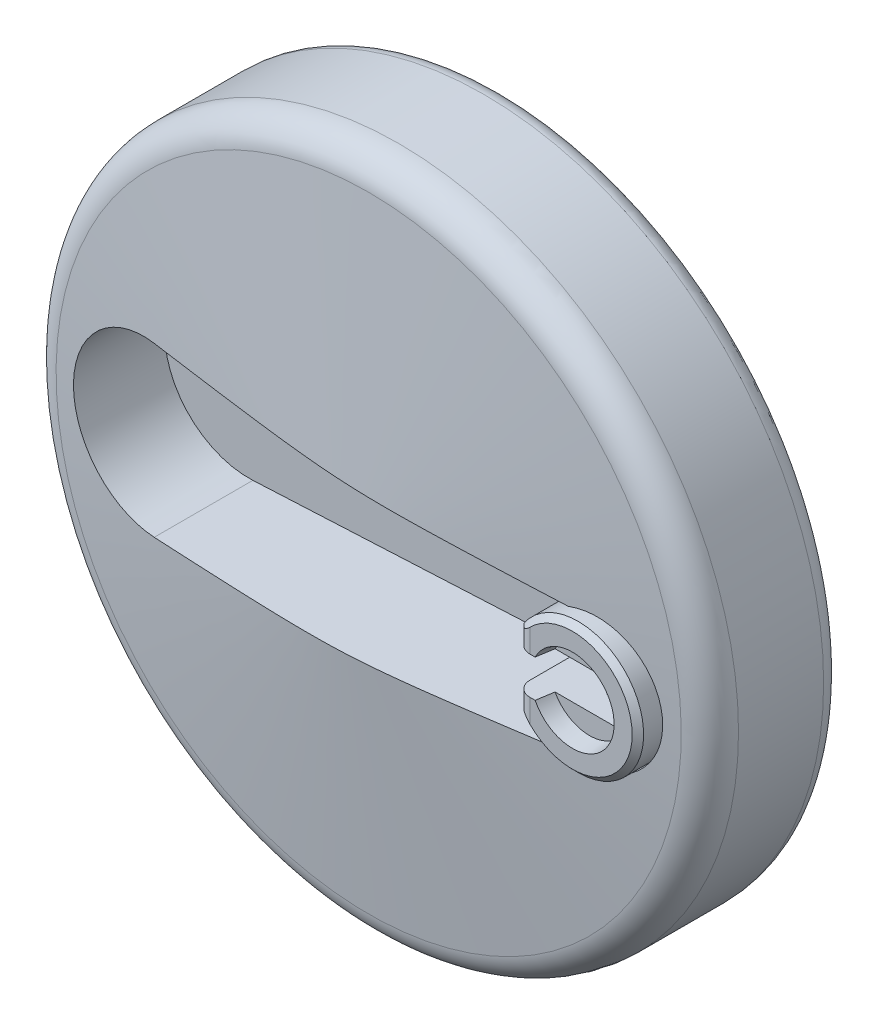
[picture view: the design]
ISO-10303-21;
HEADER;
FILE_DESCRIPTION(('STEP AP214'),'2;1');
FILE_NAME('part.step','',(''),(''),'','','');
FILE_SCHEMA(('AUTOMOTIVE_DESIGN { 1 0 10303 214 1 1 1 1 }'));
ENDSEC;
DATA;
#1=APPLICATION_CONTEXT('core data for automotive mechanical design processes');
#2=APPLICATION_PROTOCOL_DEFINITION('international standard','automotive_design',2000,#1);
#3=PRODUCT_CONTEXT('',#1,'mechanical');
#4=PRODUCT('Part','Part','',(#3));
#5=PRODUCT_RELATED_PRODUCT_CATEGORY('part','',(#4));
#6=PRODUCT_DEFINITION_FORMATION('','',#4);
#7=PRODUCT_DEFINITION_CONTEXT('part definition',#1,'design');
#8=PRODUCT_DEFINITION('design','',#6,#7);
#9=PRODUCT_DEFINITION_SHAPE('','',#8);
#10=(LENGTH_UNIT() NAMED_UNIT(*) SI_UNIT(.MILLI.,.METRE.));
#11=(NAMED_UNIT(*) PLANE_ANGLE_UNIT() SI_UNIT($,.RADIAN.));
#12=(NAMED_UNIT(*) SI_UNIT($,.STERADIAN.) SOLID_ANGLE_UNIT());
#13=UNCERTAINTY_MEASURE_WITH_UNIT(LENGTH_MEASURE(1.E-05),#10,'distance_accuracy_value','');
#14=(GEOMETRIC_REPRESENTATION_CONTEXT(3) GLOBAL_UNCERTAINTY_ASSIGNED_CONTEXT((#13)) GLOBAL_UNIT_ASSIGNED_CONTEXT((#10,
#11,#12)) REPRESENTATION_CONTEXT('',''));
#15=CARTESIAN_POINT('',(0.,0.,0.));
#16=DIRECTION('',(0.,0.,1.));
#17=DIRECTION('',(1.,0.,0.));
#18=AXIS2_PLACEMENT_3D('',#15,#16,#17);
#19=CARTESIAN_POINT('',(28.,0.,24.0000000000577));
#20=DIRECTION('',(0.,0.,-1.));
#21=DIRECTION('',(0.,-1.,0.));
#22=AXIS2_PLACEMENT_3D('',#19,#20,#21);
#23=CONICAL_SURFACE('',#22,1.99999999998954,0.785398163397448);
#24=CARTESIAN_POINT('',(28.,0.,24.));
#25=DIRECTION('',(0.,0.,1.));
#26=DIRECTION('',(0.,1.,0.));
#27=AXIS2_PLACEMENT_3D('',#24,#25,#26);
#28=CIRCLE('',#27,2.0000000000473);
#29=CARTESIAN_POINT('',(28.,2.0000000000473,24.));
#30=VERTEX_POINT('',#29);
#31=EDGE_CURVE('E27',#30,#30,#28,.T.);
#32=ORIENTED_EDGE('',*,*,#31,.F.);
#33=EDGE_LOOP('',(#32));
#34=FACE_BOUND('',#33,.T.);
#35=CARTESIAN_POINT('',(28.,0.,24.3790000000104));
#36=DIRECTION('',(0.,0.,-1.));
#37=DIRECTION('',(-1.,0.,0.));
#38=AXIS2_PLACEMENT_3D('',#35,#36,#37);
#39=CIRCLE('',#38,1.62100000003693);
#40=CARTESIAN_POINT('',(26.3789999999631,0.,24.3790000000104));
#41=VERTEX_POINT('',#40);
#42=EDGE_CURVE('E195',#41,#41,#39,.T.);
#43=ORIENTED_EDGE('',*,*,#42,.F.);
#44=EDGE_LOOP('',(#43));
#45=FACE_BOUND('',#44,.T.);
#46=ADVANCED_FACE('F16',(#34,#45),#23,.F.);
#47=CARTESIAN_POINT('',(28.,0.,26.));
#48=DIRECTION('',(0.,0.,-1.));
#49=DIRECTION('',(0.,-1.,0.));
#50=AXIS2_PLACEMENT_3D('',#47,#48,#49);
#51=CYLINDRICAL_SURFACE('',#50,1.621);
#52=ORIENTED_EDGE('',*,*,#42,.T.);
#53=EDGE_LOOP('',(#52));
#54=FACE_BOUND('',#53,.T.);
#55=CARTESIAN_POINT('',(28.,0.,27.6210000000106));
#56=DIRECTION('',(0.,0.,1.));
#57=DIRECTION('',(-1.,0.,0.));
#58=AXIS2_PLACEMENT_3D('',#55,#56,#57);
#59=CIRCLE('',#58,1.62100000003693);
#60=CARTESIAN_POINT('',(26.3789999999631,0.,27.6210000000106));
#61=VERTEX_POINT('',#60);
#62=EDGE_CURVE('E142',#61,#61,#59,.T.);
#63=ORIENTED_EDGE('',*,*,#62,.T.);
#64=EDGE_LOOP('',(#63));
#65=FACE_BOUND('',#64,.T.);
#66=ADVANCED_FACE('F249',(#54,#65),#51,.F.);
#67=CARTESIAN_POINT('',(28.,0.,30.65));
#68=DIRECTION('',(0.,0.,-1.));
#69=DIRECTION('',(0.,-1.,0.));
#70=AXIS2_PLACEMENT_3D('',#67,#68,#69);
#71=CYLINDRICAL_SURFACE('',#70,8.);
#72=CARTESIAN_POINT('',(29.6,7.83836717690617,31.5675675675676));
#73=CARTESIAN_POINT('',(29.5999957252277,7.83836939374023,31.6563778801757));
#74=CARTESIAN_POINT('',(29.5925737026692,7.83989440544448,31.7452985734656));
#75=CARTESIAN_POINT('',(29.5630860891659,7.84582557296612,31.9206956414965));
#76=CARTESIAN_POINT('',(29.540991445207,7.85023744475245,32.0071668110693));
#77=CARTESIAN_POINT('',(29.4828692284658,7.86142276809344,32.1749958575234));
#78=CARTESIAN_POINT('',(29.4468618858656,7.86819278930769,32.2563609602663));
#79=CARTESIAN_POINT('',(29.3619853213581,7.88332705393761,32.411868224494));
#80=CARTESIAN_POINT('',(29.3131203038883,7.89169077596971,32.4860127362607));
#81=CARTESIAN_POINT('',(29.2031679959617,7.90920456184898,32.6260630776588));
#82=CARTESIAN_POINT('',(29.1419323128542,7.91836331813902,32.6918513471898));
#83=CARTESIAN_POINT('',(29.0092946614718,7.93635908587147,32.8122967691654));
#84=CARTESIAN_POINT('',(28.937891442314,7.9451960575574,32.8669525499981));
#85=CARTESIAN_POINT('',(28.786177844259,7.96164477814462,32.9640285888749));
#86=CARTESIAN_POINT('',(28.7057954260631,7.96924520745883,33.0063383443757));
#87=CARTESIAN_POINT('',(28.538885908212,7.9822678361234,33.0768077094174));
#88=CARTESIAN_POINT('',(28.4523594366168,7.98769025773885,33.1049687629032));
#89=CARTESIAN_POINT('',(28.2768269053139,7.99568512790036,33.1459790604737));
#90=CARTESIAN_POINT('',(28.1878685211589,7.99829417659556,33.1590251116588));
#91=CARTESIAN_POINT('',(28.0089898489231,8.00049473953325,33.1700490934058));
#92=CARTESIAN_POINT('',(27.9190696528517,8.00008653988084,33.1680284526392));
#93=CARTESIAN_POINT('',(27.7421731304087,7.99632696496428,33.1491257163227));
#94=CARTESIAN_POINT('',(27.6551731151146,7.99301759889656,33.1324557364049));
#95=CARTESIAN_POINT('',(27.4852300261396,7.98387487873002,33.0850637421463));
#96=CARTESIAN_POINT('',(27.4022871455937,7.97804140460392,33.0543410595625));
#97=CARTESIAN_POINT('',(27.2422059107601,7.9644364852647,32.9795181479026));
#98=CARTESIAN_POINT('',(27.1651076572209,7.95665299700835,32.9353344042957));
#99=CARTESIAN_POINT('',(27.0193468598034,7.94000685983,32.8349088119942));
#100=CARTESIAN_POINT('',(26.9506846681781,7.93114416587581,32.7786664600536));
#101=CARTESIAN_POINT('',(26.8224914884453,7.91313735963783,32.6545674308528));
#102=CARTESIAN_POINT('',(26.7631384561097,7.90399103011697,32.5865271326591));
#103=CARTESIAN_POINT('',(26.6566304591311,7.88658867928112,32.4413329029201));
#104=CARTESIAN_POINT('',(26.6094809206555,7.87833305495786,32.3641749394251));
#105=CARTESIAN_POINT('',(26.5286594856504,7.86364139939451,32.202658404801));
#106=CARTESIAN_POINT('',(26.4950274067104,7.85721076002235,32.1182794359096));
#107=CARTESIAN_POINT('',(26.4425364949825,7.84697610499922,31.9450179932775));
#108=CARTESIAN_POINT('',(26.4236465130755,7.84316655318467,31.856145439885));
#109=CARTESIAN_POINT('',(26.4082711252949,7.84005162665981,31.7334243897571));
#110=CARTESIAN_POINT('',(26.4051721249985,7.83942144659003,31.7003365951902));
#111=CARTESIAN_POINT('',(26.4010357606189,7.83857880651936,31.6340268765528));
#112=CARTESIAN_POINT('',(26.3999984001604,7.8383663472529,31.6008049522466));
#113=CARTESIAN_POINT('',(26.4000042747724,7.83836939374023,31.4787572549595));
#114=CARTESIAN_POINT('',(26.4074262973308,7.83989440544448,31.3898365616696));
#115=CARTESIAN_POINT('',(26.4369139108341,7.84582557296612,31.2144394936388));
#116=CARTESIAN_POINT('',(26.459008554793,7.85023744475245,31.1279683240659));
#117=CARTESIAN_POINT('',(26.5171307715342,7.86142276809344,30.9601392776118));
#118=CARTESIAN_POINT('',(26.5531381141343,7.86819278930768,30.878774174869));
#119=CARTESIAN_POINT('',(26.6380146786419,7.88332705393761,30.7232669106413));
#120=CARTESIAN_POINT('',(26.6868796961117,7.89169077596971,30.6491223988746));
#121=CARTESIAN_POINT('',(26.7968320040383,7.90920456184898,30.5090720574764));
#122=CARTESIAN_POINT('',(26.8580676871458,7.91836331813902,30.4432837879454));
#123=CARTESIAN_POINT('',(26.9907053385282,7.93635908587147,30.3228383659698));
#124=CARTESIAN_POINT('',(27.062108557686,7.9451960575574,30.2681825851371));
#125=CARTESIAN_POINT('',(27.213822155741,7.96164477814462,30.1711065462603));
#126=CARTESIAN_POINT('',(27.2942045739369,7.96924520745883,30.1287967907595));
#127=CARTESIAN_POINT('',(27.461114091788,7.9822678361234,30.0583274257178));
#128=CARTESIAN_POINT('',(27.5476405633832,7.98769025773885,30.030166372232));
#129=CARTESIAN_POINT('',(27.7231730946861,7.99568512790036,29.9891560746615));
#130=CARTESIAN_POINT('',(27.8121314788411,7.99829417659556,29.9761100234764));
#131=CARTESIAN_POINT('',(27.9910101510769,8.00049473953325,29.9650860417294));
#132=CARTESIAN_POINT('',(28.0809303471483,8.00008653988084,29.967106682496));
#133=CARTESIAN_POINT('',(28.2578268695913,7.99632696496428,29.9860094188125));
#134=CARTESIAN_POINT('',(28.3448268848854,7.99301759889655,30.0026793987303));
#135=CARTESIAN_POINT('',(28.5147699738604,7.98387487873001,30.0500713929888));
#136=CARTESIAN_POINT('',(28.5977128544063,7.97804140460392,30.0807940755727));
#137=CARTESIAN_POINT('',(28.7577940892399,7.9644364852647,30.1556169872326));
#138=CARTESIAN_POINT('',(28.8348923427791,7.95665299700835,30.1998007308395));
#139=CARTESIAN_POINT('',(28.9806531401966,7.94000685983,30.300226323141));
#140=CARTESIAN_POINT('',(29.0493153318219,7.93114416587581,30.3564686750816));
#141=CARTESIAN_POINT('',(29.1775085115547,7.91313735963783,30.4805677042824));
#142=CARTESIAN_POINT('',(29.2368615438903,7.90399103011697,30.5486080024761));
#143=CARTESIAN_POINT('',(29.3433695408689,7.88658867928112,30.6938022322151));
#144=CARTESIAN_POINT('',(29.3905190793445,7.87833305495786,30.7709601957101));
#145=CARTESIAN_POINT('',(29.4713405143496,7.86364139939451,30.9324767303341));
#146=CARTESIAN_POINT('',(29.5049725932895,7.85721076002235,31.0168556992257));
#147=CARTESIAN_POINT('',(29.5574635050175,7.84697610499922,31.1901171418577));
#148=CARTESIAN_POINT('',(29.5763534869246,7.84316655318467,31.2789896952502));
#149=CARTESIAN_POINT('',(29.5917288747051,7.84005162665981,31.4017107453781));
#150=CARTESIAN_POINT('',(29.5948278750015,7.83942144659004,31.434798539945));
#151=CARTESIAN_POINT('',(29.5989642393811,7.83857880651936,31.5011082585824));
#152=CARTESIAN_POINT('',(29.6000015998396,7.8383663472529,31.5343301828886));
#153=CARTESIAN_POINT('',(29.6,7.83836717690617,31.5675675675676));
#154=B_SPLINE_CURVE_WITH_KNOTS('',3,(#72,#73,#74,#75,#76,#77,#78,#79,#80,#81,#82,#83,#84,#85,
#86,#87,#88,#89,#90,#91,#92,#93,#94,#95,#96,#97,#98,#99,#100,#101,#102,#103,#104,#105,#106,#107,
#108,#109,#110,#111,#112,#113,#114,#115,#116,#117,#118,#119,#120,#121,#122,#123,#124,#125,#126,
#127,#128,#129,#130,#131,#132,#133,#134,#135,#136,#137,#138,#139,#140,#141,#142,#143,#144,#145,
#146,#147,#148,#149,#150,#151,#152,#153),.UNSPECIFIED.,.T.,.F.,(4,2,2,2,2,2,2,2,2,2,2,2,2,2,2,2,
2,2,2,2,2,2,2,2,2,2,2,2,2,2,2,2,2,2,2,2,2,2,2,2,4),(0.,0.266303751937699,0.533136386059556,
0.799582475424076,1.06594154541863,1.33570888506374,1.60550944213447,1.87765555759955,
2.14977389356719,2.41830777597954,2.68681619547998,2.95149963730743,3.21619566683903,
3.48256856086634,3.74895257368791,4.01993197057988,4.29103164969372,4.56292413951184,
4.83424057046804,4.93390494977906,5.03356950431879,5.29987325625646,5.56670589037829,
5.83315197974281,6.09951104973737,6.3692783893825,6.63907894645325,6.91122506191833,
7.18334339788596,7.45187728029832,7.72038569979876,7.98506914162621,8.24976517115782,
8.51613806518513,8.7825220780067,9.05350147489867,9.32460115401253,9.59649364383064,
9.86781007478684,9.96747445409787,10.0671390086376),.UNSPECIFIED.);
#155=CARTESIAN_POINT('',(29.6,7.83836717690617,31.5675675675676));
#156=VERTEX_POINT('',#155);
#157=EDGE_CURVE('E230',#156,#156,#154,.T.);
#158=ORIENTED_EDGE('',*,*,#157,.T.);
#159=EDGE_LOOP('',(#158));
#160=FACE_BOUND('',#159,.T.);
#161=CARTESIAN_POINT('',(21.3854268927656,4.49971361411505,37.3));
#162=CARTESIAN_POINT('',(21.3611186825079,4.46398733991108,37.2688460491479));
#163=CARTESIAN_POINT('',(21.3375430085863,4.42870188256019,37.2365745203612));
#164=CARTESIAN_POINT('',(21.2919472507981,4.35932799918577,37.1695025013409));
#165=CARTESIAN_POINT('',(21.2699317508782,4.32524323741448,37.1346951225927));
#166=CARTESIAN_POINT('',(21.2271401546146,4.2579341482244,37.0614976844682));
#167=CARTESIAN_POINT('',(21.2064107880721,4.22475481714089,37.0230382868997));
#168=CARTESIAN_POINT('',(21.1671165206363,4.16090210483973,36.9431236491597));
#169=CARTESIAN_POINT('',(21.1485490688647,4.13022578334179,36.9016720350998));
#170=CARTESIAN_POINT('',(21.111194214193,4.0676625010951,36.8087047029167));
#171=CARTESIAN_POINT('',(21.092827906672,4.03633854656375,36.7566295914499));
#172=CARTESIAN_POINT('',(21.0604254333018,3.98036944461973,36.6484532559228));
#173=CARTESIAN_POINT('',(21.0463433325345,3.95565381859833,36.5924033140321));
#174=CARTESIAN_POINT('',(21.0237726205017,3.91570759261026,36.4786073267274));
#175=CARTESIAN_POINT('',(21.0150693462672,3.90011453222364,36.421038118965));
#176=CARTESIAN_POINT('',(21.0061393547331,3.88406371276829,36.3323796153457));
#177=CARTESIAN_POINT('',(21.0038487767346,3.87993353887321,36.3021352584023));
#178=CARTESIAN_POINT('',(21.0007746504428,3.87438362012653,36.2412691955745));
#179=CARTESIAN_POINT('',(20.9999938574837,3.87296883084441,36.2106469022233));
#180=CARTESIAN_POINT('',(21.,3.87298334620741,36.18));
#181=B_SPLINE_CURVE_WITH_KNOTS('',3,(#161,#162,#163,#164,#165,#166,#167,#168,#169,#170,#171,
#172,#173,#174,#175,#176,#177,#178,#179,#180),.UNSPECIFIED.,.F.,.F.,(4,2,2,2,2,2,2,2,2,4),(0.,
0.159829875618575,0.320111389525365,0.484534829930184,0.648762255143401,0.838713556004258,
1.02654994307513,1.20630161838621,1.29798861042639,1.38984277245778),.UNSPECIFIED.);
#182=CARTESIAN_POINT('',(21.3854268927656,4.49971361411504,37.3));
#183=VERTEX_POINT('',#182);
#184=CARTESIAN_POINT('',(21.,3.87298334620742,36.18));
#185=VERTEX_POINT('',#184);
#186=EDGE_CURVE('E452',#183,#185,#181,.T.);
#187=ORIENTED_EDGE('',*,*,#186,.F.);
#188=CARTESIAN_POINT('',(28.,0.,37.3));
#189=DIRECTION('',(0.,0.,-1.));
#190=DIRECTION('',(0.,-1.,0.));
#191=AXIS2_PLACEMENT_3D('',#188,#189,#190);
#192=CIRCLE('',#191,8.);
#193=CARTESIAN_POINT('',(21.3854268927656,-4.49971361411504,37.3));
#194=VERTEX_POINT('',#193);
#195=EDGE_CURVE('E239',#183,#194,#192,.T.);
#196=ORIENTED_EDGE('',*,*,#195,.T.);
#197=CARTESIAN_POINT('',(21.,-3.87298334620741,36.18));
#198=CARTESIAN_POINT('',(20.9999958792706,-3.8729737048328,36.207562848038));
#199=CARTESIAN_POINT('',(21.0006265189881,-3.87411585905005,36.2351094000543));
#200=CARTESIAN_POINT('',(21.0031168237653,-3.8786126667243,36.2899285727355));
#201=CARTESIAN_POINT('',(21.0049748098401,-3.88196429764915,36.3172015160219));
#202=CARTESIAN_POINT('',(21.0122441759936,-3.89504420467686,36.3973946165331));
#203=CARTESIAN_POINT('',(21.0193544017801,-3.90780488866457,36.4496875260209));
#204=CARTESIAN_POINT('',(21.0401857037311,-3.94481264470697,36.5661627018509));
#205=CARTESIAN_POINT('',(21.0552301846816,-3.97132453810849,36.6293633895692));
#206=CARTESIAN_POINT('',(21.0906745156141,-4.03267717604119,36.7508812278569));
#207=CARTESIAN_POINT('',(21.1111424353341,-4.06762324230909,36.8091229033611));
#208=CARTESIAN_POINT('',(21.1509293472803,-4.13417101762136,36.9071214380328));
#209=CARTESIAN_POINT('',(21.1693987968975,-4.16464542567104,36.9480171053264));
#210=CARTESIAN_POINT('',(21.2084417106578,-4.22801629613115,37.0268870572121));
#211=CARTESIAN_POINT('',(21.2290173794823,-4.26091528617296,37.0648582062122));
#212=CARTESIAN_POINT('',(21.2713947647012,-4.32751466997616,37.1370401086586));
#213=CARTESIAN_POINT('',(21.2931453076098,-4.36116603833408,37.1713268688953));
#214=CARTESIAN_POINT('',(21.3381709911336,-4.42964143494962,37.2374343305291));
#215=CARTESIAN_POINT('',(21.3614420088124,-4.46446217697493,37.2692612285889));
#216=CARTESIAN_POINT('',(21.3854268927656,-4.49971361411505,37.3));
#217=B_SPLINE_CURVE_WITH_KNOTS('',3,(#197,#198,#199,#200,#201,#202,#203,#204,#205,#206,#207,
#208,#209,#210,#211,#212,#213,#214,#215,#216),.UNSPECIFIED.,.F.,.F.,(4,2,2,2,2,2,2,2,2,4),(0.,
0.0826282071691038,0.165143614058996,0.327223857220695,0.536584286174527,0.748708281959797,
0.91125442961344,1.07397249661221,1.23208581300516,1.3897868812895),.UNSPECIFIED.);
#218=CARTESIAN_POINT('',(21.,-3.87298334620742,36.18));
#219=VERTEX_POINT('',#218);
#220=EDGE_CURVE('E199',#219,#194,#217,.T.);
#221=ORIENTED_EDGE('',*,*,#220,.F.);
#222=DIRECTION('',(0.,0.,-1.));
#223=VECTOR('',#222,1.);
#224=CARTESIAN_POINT('',(21.,-3.87298334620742,36.18));
#225=LINE('',#224,#223);
#226=CARTESIAN_POINT('',(21.,-3.87298334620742,24.));
#227=VERTEX_POINT('',#226);
#228=EDGE_CURVE('E177',#219,#227,#225,.T.);
#229=ORIENTED_EDGE('',*,*,#228,.T.);
#230=CARTESIAN_POINT('',(28.,0.,24.));
#231=DIRECTION('',(0.,0.,1.));
#232=DIRECTION('',(0.,1.,0.));
#233=AXIS2_PLACEMENT_3D('',#230,#231,#232);
#234=CIRCLE('',#233,8.);
#235=CARTESIAN_POINT('',(21.7550020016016,-5.,24.));
#236=VERTEX_POINT('',#235);
#237=EDGE_CURVE('E521',#227,#236,#234,.T.);
#238=ORIENTED_EDGE('',*,*,#237,.T.);
#239=DIRECTION('',(0.,0.,-1.));
#240=VECTOR('',#239,1.);
#241=CARTESIAN_POINT('',(21.7550020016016,-5.,30.65));
#242=LINE('',#241,#240);
#243=CARTESIAN_POINT('',(21.7550020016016,-5.,25.7));
#244=VERTEX_POINT('',#243);
#245=EDGE_CURVE('E186',#236,#244,#242,.F.);
#246=ORIENTED_EDGE('',*,*,#245,.T.);
#247=CARTESIAN_POINT('',(28.,0.,25.7));
#248=DIRECTION('',(0.,0.,-1.));
#249=DIRECTION('',(0.,-1.,0.));
#250=AXIS2_PLACEMENT_3D('',#247,#248,#249);
#251=CIRCLE('',#250,8.);
#252=CARTESIAN_POINT('',(34.2449979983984,-5.,25.7));
#253=VERTEX_POINT('',#252);
#254=EDGE_CURVE('E189',#244,#253,#251,.F.);
#255=ORIENTED_EDGE('',*,*,#254,.T.);
#256=DIRECTION('',(0.,0.,-1.));
#257=VECTOR('',#256,1.);
#258=CARTESIAN_POINT('',(34.2449979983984,-5.,30.65));
#259=LINE('',#258,#257);
#260=CARTESIAN_POINT('',(34.2449979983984,-5.,24.));
#261=VERTEX_POINT('',#260);
#262=EDGE_CURVE('E191',#253,#261,#259,.T.);
#263=ORIENTED_EDGE('',*,*,#262,.T.);
#264=CARTESIAN_POINT('',(34.2449979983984,5.,24.));
#265=VERTEX_POINT('',#264);
#266=EDGE_CURVE('E525',#261,#265,#234,.T.);
#267=ORIENTED_EDGE('',*,*,#266,.T.);
#268=DIRECTION('',(0.,0.,1.));
#269=VECTOR('',#268,1.);
#270=CARTESIAN_POINT('',(34.2449979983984,5.,24.));
#271=LINE('',#270,#269);
#272=CARTESIAN_POINT('',(34.2449979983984,5.,25.7));
#273=VERTEX_POINT('',#272);
#274=EDGE_CURVE('E183',#265,#273,#271,.T.);
#275=ORIENTED_EDGE('',*,*,#274,.T.);
#276=CARTESIAN_POINT('',(28.,0.,25.7));
#277=DIRECTION('',(0.,0.,-1.));
#278=DIRECTION('',(0.,-1.,0.));
#279=AXIS2_PLACEMENT_3D('',#276,#277,#278);
#280=CIRCLE('',#279,8.);
#281=CARTESIAN_POINT('',(21.7550020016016,5.,25.7));
#282=VERTEX_POINT('',#281);
#283=EDGE_CURVE('E240',#273,#282,#280,.F.);
#284=ORIENTED_EDGE('',*,*,#283,.T.);
#285=DIRECTION('',(0.,0.,1.));
#286=VECTOR('',#285,1.);
#287=CARTESIAN_POINT('',(21.7550020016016,5.,24.));
#288=LINE('',#287,#286);
#289=CARTESIAN_POINT('',(21.7550020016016,5.,24.));
#290=VERTEX_POINT('',#289);
#291=EDGE_CURVE('E181',#282,#290,#288,.F.);
#292=ORIENTED_EDGE('',*,*,#291,.T.);
#293=CARTESIAN_POINT('',(21.,3.87298334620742,24.));
#294=VERTEX_POINT('',#293);
#295=EDGE_CURVE('E36',#290,#294,#234,.T.);
#296=ORIENTED_EDGE('',*,*,#295,.T.);
#297=DIRECTION('',(0.,0.,-1.));
#298=VECTOR('',#297,1.);
#299=CARTESIAN_POINT('',(21.,3.87298334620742,30.65));
#300=LINE('',#299,#298);
#301=EDGE_CURVE('E509',#294,#185,#300,.F.);
#302=ORIENTED_EDGE('',*,*,#301,.T.);
#303=EDGE_LOOP('',(#187,#196,#221,#229,#238,#246,#255,#263,#267,#275,#284,#292,#296,#302));
#304=FACE_BOUND('',#303,.T.);
#305=CARTESIAN_POINT('',(26.4,-7.83836717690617,31.5675675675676));
#306=CARTESIAN_POINT('',(26.4000042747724,-7.83836939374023,31.6563778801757));
#307=CARTESIAN_POINT('',(26.4074262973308,-7.83989440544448,31.7452985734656));
#308=CARTESIAN_POINT('',(26.4369139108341,-7.84582557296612,31.9206956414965));
#309=CARTESIAN_POINT('',(26.459008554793,-7.85023744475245,32.0071668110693));
#310=CARTESIAN_POINT('',(26.5171307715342,-7.86142276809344,32.1749958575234));
#311=CARTESIAN_POINT('',(26.5531381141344,-7.86819278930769,32.2563609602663));
#312=CARTESIAN_POINT('',(26.6380146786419,-7.88332705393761,32.411868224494));
#313=CARTESIAN_POINT('',(26.6868796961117,-7.89169077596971,32.4860127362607));
#314=CARTESIAN_POINT('',(26.7968320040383,-7.90920456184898,32.6260630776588));
#315=CARTESIAN_POINT('',(26.8580676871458,-7.91836331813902,32.6918513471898));
#316=CARTESIAN_POINT('',(26.9907053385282,-7.93635908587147,32.8122967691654));
#317=CARTESIAN_POINT('',(27.0621085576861,-7.94519605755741,32.8669525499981));
#318=CARTESIAN_POINT('',(27.213822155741,-7.96164477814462,32.9640285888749));
#319=CARTESIAN_POINT('',(27.2942045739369,-7.96924520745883,33.0063383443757));
#320=CARTESIAN_POINT('',(27.461114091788,-7.9822678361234,33.0768077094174));
#321=CARTESIAN_POINT('',(27.5476405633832,-7.98769025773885,33.1049687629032));
#322=CARTESIAN_POINT('',(27.7231730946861,-7.99568512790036,33.1459790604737));
#323=CARTESIAN_POINT('',(27.8121314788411,-7.99829417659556,33.1590251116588));
#324=CARTESIAN_POINT('',(27.9910101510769,-8.00049473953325,33.1700490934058));
#325=CARTESIAN_POINT('',(28.0809303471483,-8.00008653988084,33.1680284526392));
#326=CARTESIAN_POINT('',(28.2578268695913,-7.99632696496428,33.1491257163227));
#327=CARTESIAN_POINT('',(28.3448268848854,-7.99301759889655,33.1324557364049));
#328=CARTESIAN_POINT('',(28.5147699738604,-7.98387487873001,33.0850637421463));
#329=CARTESIAN_POINT('',(28.5977128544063,-7.97804140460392,33.0543410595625));
#330=CARTESIAN_POINT('',(28.7577940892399,-7.9644364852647,32.9795181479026));
#331=CARTESIAN_POINT('',(28.8348923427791,-7.95665299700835,32.9353344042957));
#332=CARTESIAN_POINT('',(28.9806531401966,-7.94000685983,32.8349088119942));
#333=CARTESIAN_POINT('',(29.0493153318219,-7.93114416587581,32.7786664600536));
#334=CARTESIAN_POINT('',(29.1775085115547,-7.91313735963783,32.6545674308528));
#335=CARTESIAN_POINT('',(29.2368615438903,-7.90399103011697,32.5865271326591));
#336=CARTESIAN_POINT('',(29.3433695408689,-7.88658867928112,32.4413329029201));
#337=CARTESIAN_POINT('',(29.3905190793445,-7.87833305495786,32.3641749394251));
#338=CARTESIAN_POINT('',(29.4713405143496,-7.86364139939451,32.2026584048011));
#339=CARTESIAN_POINT('',(29.5049725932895,-7.85721076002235,32.1182794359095));
#340=CARTESIAN_POINT('',(29.5574635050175,-7.84697610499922,31.9450179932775));
#341=CARTESIAN_POINT('',(29.5763534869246,-7.84316655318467,31.856145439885));
#342=CARTESIAN_POINT('',(29.5917288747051,-7.84005162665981,31.7334243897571));
#343=CARTESIAN_POINT('',(29.5948278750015,-7.83942144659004,31.7003365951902));
#344=CARTESIAN_POINT('',(29.5989642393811,-7.83857880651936,31.6340268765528));
#345=CARTESIAN_POINT('',(29.6000015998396,-7.8383663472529,31.6008049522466));
#346=CARTESIAN_POINT('',(29.5999957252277,-7.83836939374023,31.4787572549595));
#347=CARTESIAN_POINT('',(29.5925737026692,-7.83989440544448,31.3898365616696));
#348=CARTESIAN_POINT('',(29.5630860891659,-7.84582557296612,31.2144394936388));
#349=CARTESIAN_POINT('',(29.540991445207,-7.85023744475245,31.1279683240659));
#350=CARTESIAN_POINT('',(29.4828692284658,-7.86142276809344,30.9601392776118));
#351=CARTESIAN_POINT('',(29.4468618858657,-7.86819278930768,30.878774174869));
#352=CARTESIAN_POINT('',(29.3619853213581,-7.8833270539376,30.7232669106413));
#353=CARTESIAN_POINT('',(29.3131203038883,-7.89169077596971,30.6491223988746));
#354=CARTESIAN_POINT('',(29.2031679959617,-7.90920456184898,30.5090720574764));
#355=CARTESIAN_POINT('',(29.1419323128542,-7.91836331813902,30.4432837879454));
#356=CARTESIAN_POINT('',(29.0092946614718,-7.93635908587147,30.3228383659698));
#357=CARTESIAN_POINT('',(28.937891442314,-7.9451960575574,30.2681825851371));
#358=CARTESIAN_POINT('',(28.786177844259,-7.96164477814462,30.1711065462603));
#359=CARTESIAN_POINT('',(28.7057954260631,-7.96924520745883,30.1287967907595));
#360=CARTESIAN_POINT('',(28.538885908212,-7.9822678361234,30.0583274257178));
#361=CARTESIAN_POINT('',(28.4523594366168,-7.98769025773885,30.030166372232));
#362=CARTESIAN_POINT('',(28.2768269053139,-7.99568512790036,29.9891560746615));
#363=CARTESIAN_POINT('',(28.1878685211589,-7.99829417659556,29.9761100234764));
#364=CARTESIAN_POINT('',(28.0089898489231,-8.00049473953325,29.9650860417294));
#365=CARTESIAN_POINT('',(27.9190696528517,-8.00008653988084,29.967106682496));
#366=CARTESIAN_POINT('',(27.7421731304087,-7.99632696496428,29.9860094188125));
#367=CARTESIAN_POINT('',(27.6551731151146,-7.99301759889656,30.0026793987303));
#368=CARTESIAN_POINT('',(27.4852300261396,-7.98387487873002,30.0500713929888));
#369=CARTESIAN_POINT('',(27.4022871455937,-7.97804140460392,30.0807940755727));
#370=CARTESIAN_POINT('',(27.2422059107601,-7.9644364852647,30.1556169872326));
#371=CARTESIAN_POINT('',(27.1651076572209,-7.95665299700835,30.1998007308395));
#372=CARTESIAN_POINT('',(27.0193468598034,-7.94000685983,30.300226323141));
#373=CARTESIAN_POINT('',(26.9506846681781,-7.93114416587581,30.3564686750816));
#374=CARTESIAN_POINT('',(26.8224914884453,-7.91313735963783,30.4805677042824));
#375=CARTESIAN_POINT('',(26.7631384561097,-7.90399103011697,30.5486080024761));
#376=CARTESIAN_POINT('',(26.6566304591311,-7.88658867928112,30.6938022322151));
#377=CARTESIAN_POINT('',(26.6094809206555,-7.87833305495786,30.7709601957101));
#378=CARTESIAN_POINT('',(26.5286594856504,-7.86364139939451,30.9324767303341));
#379=CARTESIAN_POINT('',(26.4950274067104,-7.85721076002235,31.0168556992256));
#380=CARTESIAN_POINT('',(26.4425364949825,-7.84697610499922,31.1901171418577));
#381=CARTESIAN_POINT('',(26.4236465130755,-7.84316655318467,31.2789896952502));
#382=CARTESIAN_POINT('',(26.4082711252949,-7.84005162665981,31.4017107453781));
#383=CARTESIAN_POINT('',(26.4051721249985,-7.83942144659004,31.434798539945));
#384=CARTESIAN_POINT('',(26.4010357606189,-7.83857880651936,31.5011082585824));
#385=CARTESIAN_POINT('',(26.3999984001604,-7.8383663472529,31.5343301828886));
#386=CARTESIAN_POINT('',(26.4,-7.83836717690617,31.5675675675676));
#387=B_SPLINE_CURVE_WITH_KNOTS('',3,(#305,#306,#307,#308,#309,#310,#311,#312,#313,#314,#315,
#316,#317,#318,#319,#320,#321,#322,#323,#324,#325,#326,#327,#328,#329,#330,#331,#332,#333,#334,
#335,#336,#337,#338,#339,#340,#341,#342,#343,#344,#345,#346,#347,#348,#349,#350,#351,#352,#353,
#354,#355,#356,#357,#358,#359,#360,#361,#362,#363,#364,#365,#366,#367,#368,#369,#370,#371,#372,
#373,#374,#375,#376,#377,#378,#379,#380,#381,#382,#383,#384,#385,#386),.UNSPECIFIED.,.T.,.F.,(4,
2,2,2,2,2,2,2,2,2,2,2,2,2,2,2,2,2,2,2,2,2,2,2,2,2,2,2,2,2,2,2,2,2,2,2,2,2,2,2,4),(0.,
0.266303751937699,0.533136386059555,0.799582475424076,1.06594154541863,1.33570888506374,
1.60550944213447,1.87765555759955,2.14977389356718,2.41830777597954,2.68681619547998,
2.95149963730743,3.21619566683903,3.48256856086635,3.74895257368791,4.01993197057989,
4.29103164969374,4.56292413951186,4.83424057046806,4.93390494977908,5.03356950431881,
5.29987325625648,5.56670589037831,5.83315197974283,6.09951104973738,6.36927838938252,
6.63907894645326,6.91122506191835,7.18334339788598,7.45187728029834,7.72038569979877,
7.98506914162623,8.24976517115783,8.51613806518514,8.78252207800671,9.05350147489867,
9.32460115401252,9.59649364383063,9.86781007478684,9.96747445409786,10.0671390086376),.UNSPECIFIED.);
#388=CARTESIAN_POINT('',(26.4,-7.83836717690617,31.5675675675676));
#389=VERTEX_POINT('',#388);
#390=EDGE_CURVE('E190',#389,#389,#387,.T.);
#391=ORIENTED_EDGE('',*,*,#390,.T.);
#392=EDGE_LOOP('',(#391));
#393=FACE_BOUND('',#392,.T.);
#394=ADVANCED_FACE('F245',(#160,#304,#393),#71,.T.);
#395=CARTESIAN_POINT('',(28.,16.,31.5675675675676));
#396=DIRECTION('',(0.,1.,0.));
#397=DIRECTION('',(-1.,0.,0.));
#398=AXIS2_PLACEMENT_3D('',#395,#396,#397);
#399=CYLINDRICAL_SURFACE('',#398,1.6);
#400=CARTESIAN_POINT('',(28.,7.6,31.5675675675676));
#401=DIRECTION('',(0.,1.,0.));
#402=DIRECTION('',(-1.,0.,0.));
#403=AXIS2_PLACEMENT_3D('',#400,#401,#402);
#404=CIRCLE('',#403,1.6);
#405=CARTESIAN_POINT('',(26.4,7.6,31.5675675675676));
#406=VERTEX_POINT('',#405);
#407=EDGE_CURVE('E502',#406,#406,#404,.T.);
#408=ORIENTED_EDGE('',*,*,#407,.F.);
#409=EDGE_LOOP('',(#408));
#410=FACE_BOUND('',#409,.T.);
#411=ORIENTED_EDGE('',*,*,#157,.F.);
#412=EDGE_LOOP('',(#411));
#413=FACE_BOUND('',#412,.T.);
#414=ADVANCED_FACE('F242',(#410,#413),#399,.F.);
#415=CARTESIAN_POINT('',(22.82,16.,36.18));
#416=DIRECTION('',(0.,1.,0.));
#417=DIRECTION('',(-1.,0.,0.));
#418=AXIS2_PLACEMENT_3D('',#415,#416,#417);
#419=CYLINDRICAL_SURFACE('',#418,1.82);
#420=ORIENTED_EDGE('',*,*,#186,.T.);
#421=DIRECTION('',(0.,1.,0.));
#422=VECTOR('',#421,1.);
#423=CARTESIAN_POINT('',(21.,16.,36.18));
#424=LINE('',#423,#422);
#425=CARTESIAN_POINT('',(21.,2.28571428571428,36.18));
#426=VERTEX_POINT('',#425);
#427=EDGE_CURVE('E174',#185,#426,#424,.F.);
#428=ORIENTED_EDGE('',*,*,#427,.T.);
#429=CARTESIAN_POINT('',(22.82,2.28571428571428,36.18));
#430=DIRECTION('',(0.,1.,0.));
#431=DIRECTION('',(-1.,0.,0.));
#432=AXIS2_PLACEMENT_3D('',#429,#430,#431);
#433=CIRCLE('',#432,1.82);
#434=CARTESIAN_POINT('',(22.82,2.28571428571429,38.));
#435=VERTEX_POINT('',#434);
#436=EDGE_CURVE('E209',#426,#435,#433,.T.);
#437=ORIENTED_EDGE('',*,*,#436,.T.);
#438=DIRECTION('',(0.,1.,0.));
#439=VECTOR('',#438,1.);
#440=CARTESIAN_POINT('',(22.82,0.,38.));
#441=LINE('',#440,#439);
#442=CARTESIAN_POINT('',(22.82,5.14369516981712,38.));
#443=VERTEX_POINT('',#442);
#444=EDGE_CURVE('E448',#443,#435,#441,.F.);
#445=ORIENTED_EDGE('',*,*,#444,.F.);
#446=CARTESIAN_POINT('',(21.3854268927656,4.49971361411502,37.3));
#447=CARTESIAN_POINT('',(21.4000946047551,4.48787715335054,37.3187845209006));
#448=CARTESIAN_POINT('',(21.4153868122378,4.47688445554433,37.3376117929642));
#449=CARTESIAN_POINT('',(21.4472740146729,4.45683186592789,37.3752560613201));
#450=CARTESIAN_POINT('',(21.4638713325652,4.44777553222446,37.3940729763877));
#451=CARTESIAN_POINT('',(21.5154350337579,4.42402564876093,37.4500615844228));
#452=CARTESIAN_POINT('',(21.5523287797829,4.41261971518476,37.4869738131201));
#453=CARTESIAN_POINT('',(21.6237990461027,4.4010987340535,37.5523925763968));
#454=CARTESIAN_POINT('',(21.6577798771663,4.39945166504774,37.5812910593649));
#455=CARTESIAN_POINT('',(21.727464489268,4.40323261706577,37.6362738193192));
#456=CARTESIAN_POINT('',(21.7631655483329,4.40864979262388,37.6623623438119));
#457=CARTESIAN_POINT('',(21.8439176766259,4.42771829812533,37.7170677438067));
#458=CARTESIAN_POINT('',(21.8891662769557,4.44302657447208,37.744801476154));
#459=CARTESIAN_POINT('',(21.9795413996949,4.48091064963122,37.7951550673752));
#460=CARTESIAN_POINT('',(22.0246669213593,4.50351200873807,37.8177564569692));
#461=CARTESIAN_POINT('',(22.1417649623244,4.56948823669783,37.8707762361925));
#462=CARTESIAN_POINT('',(22.2130628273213,4.61706130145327,37.8973715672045));
#463=CARTESIAN_POINT('',(22.3529727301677,4.72008521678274,37.9405876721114));
#464=CARTESIAN_POINT('',(22.4215743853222,4.77556331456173,37.957172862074));
#465=CARTESIAN_POINT('',(22.5461583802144,4.88265663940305,37.9802229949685));
#466=CARTESIAN_POINT('',(22.6025028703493,4.93362371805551,37.987824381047));
#467=CARTESIAN_POINT('',(22.712820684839,5.03741216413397,37.9976667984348));
#468=CARTESIAN_POINT('',(22.766812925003,5.09020786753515,37.9999642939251));
#469=CARTESIAN_POINT('',(22.82,5.14369516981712,38.));
#470=B_SPLINE_CURVE_WITH_KNOTS('',3,(#446,#447,#448,#449,#450,#451,#452,#453,#454,#455,#456,
#457,#458,#459,#460,#461,#462,#463,#464,#465,#466,#467,#468,#469),.UNSPECIFIED.,.F.,.F.,(4,2,2,
2,2,2,2,2,2,2,2,4),(0.,0.0797968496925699,0.159739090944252,0.318774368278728,0.451999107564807,
0.585019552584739,0.749794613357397,0.915153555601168,1.18288453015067,1.45156171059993,
1.68037511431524,1.90674115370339),.UNSPECIFIED.);
#471=EDGE_CURVE('E459',#183,#443,#470,.T.);
#472=ORIENTED_EDGE('',*,*,#471,.F.);
#473=EDGE_LOOP('',(#420,#428,#437,#445,#472));
#474=FACE_BOUND('',#473,.T.);
#475=ADVANCED_FACE('F393',(#474),#419,.T.);
#476=CARTESIAN_POINT('',(28.,0.,37.3));
#477=DIRECTION('',(0.,0.,-1.));
#478=DIRECTION('',(0.,-1.,0.));
#479=AXIS2_PLACEMENT_3D('',#476,#477,#478);
#480=CONICAL_SURFACE('',#479,8.,0.785398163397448);
#481=ORIENTED_EDGE('',*,*,#471,.T.);
#482=CARTESIAN_POINT('',(28.,0.,38.));
#483=DIRECTION('',(0.,0.,-1.));
#484=DIRECTION('',(0.,-1.,0.));
#485=AXIS2_PLACEMENT_3D('',#482,#483,#484);
#486=CIRCLE('',#485,7.3);
#487=CARTESIAN_POINT('',(22.82,-5.14369516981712,38.));
#488=VERTEX_POINT('',#487);
#489=EDGE_CURVE('E443',#443,#488,#486,.T.);
#490=ORIENTED_EDGE('',*,*,#489,.T.);
#491=CARTESIAN_POINT('',(22.82,-5.14369516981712,38.));
#492=CARTESIAN_POINT('',(22.7762484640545,-5.09966836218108,37.9999837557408));
#493=CARTESIAN_POINT('',(22.7319485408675,-5.05613969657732,37.9984212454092));
#494=CARTESIAN_POINT('',(22.6420170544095,-4.97041214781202,37.991844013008));
#495=CARTESIAN_POINT('',(22.5963811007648,-4.92821889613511,37.9868162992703));
#496=CARTESIAN_POINT('',(22.5030840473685,-4.84513381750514,37.9728257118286));
#497=CARTESIAN_POINT('',(22.4554016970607,-4.80427637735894,37.9637972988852));
#498=CARTESIAN_POINT('',(22.3587434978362,-4.72554228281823,37.9412787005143));
#499=CARTESIAN_POINT('',(22.3097699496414,-4.68766074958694,37.9277960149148));
#500=CARTESIAN_POINT('',(22.2142550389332,-4.61885364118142,37.8969140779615));
#501=CARTESIAN_POINT('',(22.1678178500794,-4.58761682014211,37.8798976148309));
#502=CARTESIAN_POINT('',(22.0739775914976,-4.53032040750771,37.8408499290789));
#503=CARTESIAN_POINT('',(22.0265777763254,-4.50424581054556,37.8188336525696));
#504=CARTESIAN_POINT('',(21.938051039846,-4.46258352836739,37.7726972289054));
#505=CARTESIAN_POINT('',(21.8969983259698,-4.44602860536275,37.7493303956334));
#506=CARTESIAN_POINT('',(21.8153259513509,-4.41999217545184,37.6983331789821));
#507=CARTESIAN_POINT('',(21.7747055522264,-4.41049561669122,37.6707120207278));
#508=CARTESIAN_POINT('',(21.6947628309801,-4.40002559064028,37.6113407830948));
#509=CARTESIAN_POINT('',(21.6554559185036,-4.39913146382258,37.5795550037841));
#510=CARTESIAN_POINT('',(21.580050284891,-4.40666247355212,37.5132109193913));
#511=CARTESIAN_POINT('',(21.5439587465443,-4.41510793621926,37.4786467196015));
#512=CARTESIAN_POINT('',(21.4872112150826,-4.43629868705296,37.4198265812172));
#513=CARTESIAN_POINT('',(21.4653439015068,-4.44676297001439,37.3958607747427));
#514=CARTESIAN_POINT('',(21.4237837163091,-4.47094093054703,37.3478970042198));
#515=CARTESIAN_POINT('',(21.404081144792,-4.48463916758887,37.3238997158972));
#516=CARTESIAN_POINT('',(21.3854268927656,-4.49971361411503,37.3));
#517=B_SPLINE_CURVE_WITH_KNOTS('',3,(#491,#492,#493,#494,#495,#496,#497,#498,#499,#500,#501,
#502,#503,#504,#505,#506,#507,#508,#509,#510,#511,#512,#513,#514,#515,#516),.UNSPECIFIED.,.F.,
.F.,(4,2,2,2,2,2,2,2,2,2,2,2,4),(0.,0.186233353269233,0.373168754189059,0.563286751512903,
0.753086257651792,0.928230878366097,1.10285866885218,1.25246795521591,1.40175727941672,
1.55242219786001,1.7034156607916,1.80546729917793,1.90704120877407),.UNSPECIFIED.);
#518=EDGE_CURVE('E223',#488,#194,#517,.T.);
#519=ORIENTED_EDGE('',*,*,#518,.T.);
#520=ORIENTED_EDGE('',*,*,#195,.F.);
#521=EDGE_LOOP('',(#481,#490,#519,#520));
#522=FACE_BOUND('',#521,.T.);
#523=ADVANCED_FACE('F421',(#522),#480,.T.);
#524=CARTESIAN_POINT('',(22.82,16.,36.18));
#525=DIRECTION('',(0.,1.,0.));
#526=DIRECTION('',(-1.,0.,0.));
#527=AXIS2_PLACEMENT_3D('',#524,#525,#526);
#528=CYLINDRICAL_SURFACE('',#527,1.82);
#529=ORIENTED_EDGE('',*,*,#518,.F.);
#530=DIRECTION('',(0.,1.,0.));
#531=VECTOR('',#530,1.);
#532=CARTESIAN_POINT('',(22.82,0.,38.));
#533=LINE('',#532,#531);
#534=CARTESIAN_POINT('',(22.82,-2.28571428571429,38.));
#535=VERTEX_POINT('',#534);
#536=EDGE_CURVE('E437',#535,#488,#533,.F.);
#537=ORIENTED_EDGE('',*,*,#536,.F.);
#538=CARTESIAN_POINT('',(22.82,-2.28571428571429,36.18));
#539=DIRECTION('',(0.,1.,0.));
#540=DIRECTION('',(-1.,0.,0.));
#541=AXIS2_PLACEMENT_3D('',#538,#539,#540);
#542=CIRCLE('',#541,1.82);
#543=CARTESIAN_POINT('',(21.,-2.28571428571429,36.18));
#544=VERTEX_POINT('',#543);
#545=EDGE_CURVE('E464',#535,#544,#542,.F.);
#546=ORIENTED_EDGE('',*,*,#545,.T.);
#547=DIRECTION('',(0.,1.,0.));
#548=VECTOR('',#547,1.);
#549=CARTESIAN_POINT('',(21.,16.,36.18));
#550=LINE('',#549,#548);
#551=EDGE_CURVE('E196',#544,#219,#550,.F.);
#552=ORIENTED_EDGE('',*,*,#551,.T.);
#553=ORIENTED_EDGE('',*,*,#220,.T.);
#554=EDGE_LOOP('',(#529,#537,#546,#552,#553));
#555=FACE_BOUND('',#554,.T.);
#556=ADVANCED_FACE('F296',(#555),#528,.T.);
#557=CARTESIAN_POINT('',(21.,16.,36.18));
#558=DIRECTION('',(1.,0.,0.));
#559=DIRECTION('',(0.,0.,-1.));
#560=AXIS2_PLACEMENT_3D('',#557,#558,#559);
#561=PLANE('',#560);
#562=DIRECTION('',(0.,1.,0.));
#563=VECTOR('',#562,1.);
#564=CARTESIAN_POINT('',(21.,16.,28.));
#565=LINE('',#564,#563);
#566=CARTESIAN_POINT('',(21.,2.28571428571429,28.));
#567=VERTEX_POINT('',#566);
#568=CARTESIAN_POINT('',(21.,-2.28571428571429,28.));
#569=VERTEX_POINT('',#568);
#570=EDGE_CURVE('E173',#567,#569,#565,.F.);
#571=ORIENTED_EDGE('',*,*,#570,.F.);
#572=DIRECTION('',(0.,0.,-1.));
#573=VECTOR('',#572,1.);
#574=CARTESIAN_POINT('',(21.,2.28571428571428,36.18));
#575=LINE('',#574,#573);
#576=EDGE_CURVE('E158',#426,#567,#575,.T.);
#577=ORIENTED_EDGE('',*,*,#576,.F.);
#578=ORIENTED_EDGE('',*,*,#427,.F.);
#579=ORIENTED_EDGE('',*,*,#301,.F.);
#580=DIRECTION('',(0.,1.,0.));
#581=VECTOR('',#580,1.);
#582=CARTESIAN_POINT('',(21.,0.,24.));
#583=LINE('',#582,#581);
#584=EDGE_CURVE('E516',#227,#294,#583,.T.);
#585=ORIENTED_EDGE('',*,*,#584,.F.);
#586=ORIENTED_EDGE('',*,*,#228,.F.);
#587=ORIENTED_EDGE('',*,*,#551,.F.);
#588=DIRECTION('',(0.,0.,-1.));
#589=VECTOR('',#588,1.);
#590=CARTESIAN_POINT('',(21.,-2.28571428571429,36.18));
#591=LINE('',#590,#589);
#592=EDGE_CURVE('E456',#569,#544,#591,.F.);
#593=ORIENTED_EDGE('',*,*,#592,.F.);
#594=EDGE_LOOP('',(#571,#577,#578,#579,#585,#586,#587,#593));
#595=FACE_BOUND('',#594,.T.);
#596=ADVANCED_FACE('F330',(#595),#561,.F.);
#597=CARTESIAN_POINT('',(12.,-5.,25.7));
#598=DIRECTION('',(0.,1.,0.));
#599=DIRECTION('',(-1.,0.,0.));
#600=AXIS2_PLACEMENT_3D('',#597,#598,#599);
#601=PLANE('',#600);
#602=DIRECTION('',(-1.,0.,0.));
#603=VECTOR('',#602,1.);
#604=CARTESIAN_POINT('',(12.,-5.,25.7));
#605=LINE('',#604,#603);
#606=EDGE_CURVE('E184',#244,#253,#605,.F.);
#607=ORIENTED_EDGE('',*,*,#606,.F.);
#608=ORIENTED_EDGE('',*,*,#245,.F.);
#609=DIRECTION('',(-1.,0.,0.));
#610=VECTOR('',#609,1.);
#611=CARTESIAN_POINT('',(0.,-5.,24.));
#612=LINE('',#611,#610);
#613=EDGE_CURVE('E518',#261,#236,#612,.T.);
#614=ORIENTED_EDGE('',*,*,#613,.F.);
#615=ORIENTED_EDGE('',*,*,#262,.F.);
#616=EDGE_LOOP('',(#607,#608,#614,#615));
#617=FACE_BOUND('',#616,.T.);
#618=ADVANCED_FACE('F327',(#617),#601,.F.);
#619=CARTESIAN_POINT('',(12.,-10.,25.7));
#620=DIRECTION('',(0.,0.,1.));
#621=DIRECTION('',(0.,1.,0.));
#622=AXIS2_PLACEMENT_3D('',#619,#620,#621);
#623=PLANE('',#622);
#624=ORIENTED_EDGE('',*,*,#606,.T.);
#625=ORIENTED_EDGE('',*,*,#254,.F.);
#626=EDGE_LOOP('',(#624,#625));
#627=FACE_BOUND('',#626,.T.);
#628=ADVANCED_FACE('F283',(#627),#623,.F.);
#629=CARTESIAN_POINT('',(12.,5.,24.));
#630=DIRECTION('',(0.,-1.,0.));
#631=DIRECTION('',(1.,0.,0.));
#632=AXIS2_PLACEMENT_3D('',#629,#630,#631);
#633=PLANE('',#632);
#634=DIRECTION('',(1.,0.,0.));
#635=VECTOR('',#634,1.);
#636=CARTESIAN_POINT('',(0.,5.,24.));
#637=LINE('',#636,#635);
#638=EDGE_CURVE('E522',#290,#265,#637,.T.);
#639=ORIENTED_EDGE('',*,*,#638,.F.);
#640=ORIENTED_EDGE('',*,*,#291,.F.);
#641=DIRECTION('',(-1.,0.,0.));
#642=VECTOR('',#641,1.);
#643=CARTESIAN_POINT('',(12.,5.,25.7));
#644=LINE('',#643,#642);
#645=EDGE_CURVE('E180',#282,#273,#644,.F.);
#646=ORIENTED_EDGE('',*,*,#645,.T.);
#647=ORIENTED_EDGE('',*,*,#274,.F.);
#648=EDGE_LOOP('',(#639,#640,#646,#647));
#649=FACE_BOUND('',#648,.T.);
#650=ADVANCED_FACE('F323',(#649),#633,.F.);
#651=CARTESIAN_POINT('',(12.,5.,25.7));
#652=DIRECTION('',(0.,0.,1.));
#653=DIRECTION('',(0.,1.,0.));
#654=AXIS2_PLACEMENT_3D('',#651,#652,#653);
#655=PLANE('',#654);
#656=ORIENTED_EDGE('',*,*,#645,.F.);
#657=ORIENTED_EDGE('',*,*,#283,.F.);
#658=EDGE_LOOP('',(#656,#657));
#659=FACE_BOUND('',#658,.T.);
#660=ADVANCED_FACE('F281',(#659),#655,.F.);
#661=CARTESIAN_POINT('',(28.,16.,31.5675675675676));
#662=DIRECTION('',(0.,1.,0.));
#663=DIRECTION('',(-1.,0.,0.));
#664=AXIS2_PLACEMENT_3D('',#661,#662,#663);
#665=CYLINDRICAL_SURFACE('',#664,1.6);
#666=CARTESIAN_POINT('',(28.,-7.6,31.5675675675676));
#667=DIRECTION('',(0.,1.,0.));
#668=DIRECTION('',(-1.,0.,0.));
#669=AXIS2_PLACEMENT_3D('',#666,#667,#668);
#670=CIRCLE('',#669,1.6);
#671=CARTESIAN_POINT('',(26.4,-7.6,31.5675675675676));
#672=VERTEX_POINT('',#671);
#673=EDGE_CURVE('E224',#672,#672,#670,.F.);
#674=ORIENTED_EDGE('',*,*,#673,.F.);
#675=EDGE_LOOP('',(#674));
#676=FACE_BOUND('',#675,.T.);
#677=ORIENTED_EDGE('',*,*,#390,.F.);
#678=EDGE_LOOP('',(#677));
#679=FACE_BOUND('',#678,.T.);
#680=ADVANCED_FACE('F276',(#676,#679),#665,.F.);
#681=CARTESIAN_POINT('',(28.,0.,28.));
#682=DIRECTION('',(0.,0.,1.));
#683=DIRECTION('',(0.,1.,0.));
#684=AXIS2_PLACEMENT_3D('',#681,#682,#683);
#685=PLANE('',#684);
#686=CARTESIAN_POINT('',(31.0857142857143,1.37142857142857,28.));
#687=DIRECTION('',(0.,0.,-1.));
#688=DIRECTION('',(0.,-1.,0.));
#689=AXIS2_PLACEMENT_3D('',#686,#687,#688);
#690=CIRCLE('',#689,0.914285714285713);
#691=CARTESIAN_POINT('',(32.,1.37142857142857,28.));
#692=VERTEX_POINT('',#691);
#693=CARTESIAN_POINT('',(31.0857142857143,2.28571428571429,28.));
#694=VERTEX_POINT('',#693);
#695=EDGE_CURVE('E129',#692,#694,#690,.F.);
#696=ORIENTED_EDGE('',*,*,#695,.T.);
#697=DIRECTION('',(-1.,0.,0.));
#698=VECTOR('',#697,1.);
#699=CARTESIAN_POINT('',(28.,2.28571428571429,28.));
#700=LINE('',#699,#698);
#701=EDGE_CURVE('E137',#694,#567,#700,.T.);
#702=ORIENTED_EDGE('',*,*,#701,.T.);
#703=ORIENTED_EDGE('',*,*,#570,.T.);
#704=DIRECTION('',(1.,0.,0.));
#705=VECTOR('',#704,1.);
#706=CARTESIAN_POINT('',(31.0857142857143,-2.28571428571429,28.));
#707=LINE('',#706,#705);
#708=CARTESIAN_POINT('',(31.0857142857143,-2.28571428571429,28.));
#709=VERTEX_POINT('',#708);
#710=EDGE_CURVE('E207',#569,#709,#707,.T.);
#711=ORIENTED_EDGE('',*,*,#710,.T.);
#712=CARTESIAN_POINT('',(31.0857142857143,-1.37142857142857,28.));
#713=DIRECTION('',(0.,0.,-1.));
#714=DIRECTION('',(0.,-1.,0.));
#715=AXIS2_PLACEMENT_3D('',#712,#713,#714);
#716=CIRCLE('',#715,0.914285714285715);
#717=CARTESIAN_POINT('',(32.,-1.37142857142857,28.));
#718=VERTEX_POINT('',#717);
#719=EDGE_CURVE('E164',#709,#718,#716,.F.);
#720=ORIENTED_EDGE('',*,*,#719,.T.);
#721=DIRECTION('',(0.,1.,0.));
#722=VECTOR('',#721,1.);
#723=CARTESIAN_POINT('',(32.,0.,28.));
#724=LINE('',#723,#722);
#725=EDGE_CURVE('E141',#718,#692,#724,.T.);
#726=ORIENTED_EDGE('',*,*,#725,.T.);
#727=EDGE_LOOP('',(#696,#702,#703,#711,#720,#726));
#728=FACE_BOUND('',#727,.T.);
#729=CARTESIAN_POINT('',(28.,0.,28.00000000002));
#730=DIRECTION('',(0.,0.,1.));
#731=DIRECTION('',(0.,1.,0.));
#732=AXIS2_PLACEMENT_3D('',#729,#730,#731);
#733=CIRCLE('',#732,2.00000000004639);
#734=CARTESIAN_POINT('',(28.,2.00000000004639,28.00000000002));
#735=VERTEX_POINT('',#734);
#736=EDGE_CURVE('E217',#735,#735,#733,.F.);
#737=ORIENTED_EDGE('',*,*,#736,.T.);
#738=EDGE_LOOP('',(#737));
#739=FACE_BOUND('',#738,.T.);
#740=ADVANCED_FACE('F134',(#728,#739),#685,.T.);
#741=CARTESIAN_POINT('',(16.,2.28571428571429,28.));
#742=DIRECTION('',(0.,1.,0.));
#743=DIRECTION('',(-1.,0.,0.));
#744=AXIS2_PLACEMENT_3D('',#741,#742,#743);
#745=PLANE('',#744);
#746=CARTESIAN_POINT('',(23.4463291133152,2.28571428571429,38.0000000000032));
#747=CARTESIAN_POINT('',(23.5013619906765,2.28571428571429,37.6499304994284));
#748=CARTESIAN_POINT('',(23.5566141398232,2.28571428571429,37.2998957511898));
#749=CARTESIAN_POINT('',(23.6675569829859,2.28571428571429,36.5998957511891));
#750=CARTESIAN_POINT('',(23.7232476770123,2.28571428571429,36.2499304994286));
#751=CARTESIAN_POINT('',(23.7791576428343,2.28571428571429,35.9000000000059));
#752=B_SPLINE_CURVE_WITH_KNOTS('',3,(#746,#747,#748,#749,#750,#751),.UNSPECIFIED.,.F.,.F.,(4,2,
4),(0.,1.06310588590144,2.12621179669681),.UNSPECIFIED.);
#753=CARTESIAN_POINT('',(23.4463291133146,2.28571428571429,38.000000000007));
#754=VERTEX_POINT('',#753);
#755=CARTESIAN_POINT('',(23.7791576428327,2.28571428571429,35.9000000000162));
#756=VERTEX_POINT('',#755);
#757=EDGE_CURVE('E151',#754,#756,#752,.T.);
#758=ORIENTED_EDGE('',*,*,#757,.F.);
#759=DIRECTION('',(-1.,0.,0.));
#760=VECTOR('',#759,1.);
#761=CARTESIAN_POINT('',(21.8024321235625,2.28571428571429,38.));
#762=LINE('',#761,#760);
#763=EDGE_CURVE('E450',#435,#754,#762,.F.);
#764=ORIENTED_EDGE('',*,*,#763,.F.);
#765=ORIENTED_EDGE('',*,*,#436,.F.);
#766=ORIENTED_EDGE('',*,*,#576,.T.);
#767=ORIENTED_EDGE('',*,*,#701,.F.);
#768=DIRECTION('',(0.,0.,1.));
#769=VECTOR('',#768,1.);
#770=CARTESIAN_POINT('',(31.0857142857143,2.28571428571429,28.));
#771=LINE('',#770,#769);
#772=CARTESIAN_POINT('',(31.0857142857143,2.28571428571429,35.9));
#773=VERTEX_POINT('',#772);
#774=EDGE_CURVE('E144',#773,#694,#771,.F.);
#775=ORIENTED_EDGE('',*,*,#774,.F.);
#776=DIRECTION('',(-1.,0.,0.));
#777=VECTOR('',#776,1.);
#778=CARTESIAN_POINT('',(16.,2.28571428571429,35.9));
#779=LINE('',#778,#777);
#780=EDGE_CURVE('E215',#756,#773,#779,.F.);
#781=ORIENTED_EDGE('',*,*,#780,.F.);
#782=EDGE_LOOP('',(#758,#764,#765,#766,#767,#775,#781));
#783=FACE_BOUND('',#782,.T.);
#784=CARTESIAN_POINT('',(28.,2.28571428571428,31.5675675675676));
#785=DIRECTION('',(0.,-1.,0.));
#786=DIRECTION('',(1.,0.,0.));
#787=AXIS2_PLACEMENT_3D('',#784,#785,#786);
#788=CIRCLE('',#787,1.6);
#789=CARTESIAN_POINT('',(29.6,2.28571428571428,31.5675675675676));
#790=VERTEX_POINT('',#789);
#791=EDGE_CURVE('E152',#790,#790,#788,.T.);
#792=ORIENTED_EDGE('',*,*,#791,.F.);
#793=EDGE_LOOP('',(#792));
#794=FACE_BOUND('',#793,.T.);
#795=ADVANCED_FACE('F155',(#783,#794),#745,.F.);
#796=CARTESIAN_POINT('',(31.0857142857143,-2.28571428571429,28.));
#797=DIRECTION('',(0.,-1.,0.));
#798=DIRECTION('',(1.,0.,0.));
#799=AXIS2_PLACEMENT_3D('',#796,#797,#798);
#800=PLANE('',#799);
#801=DIRECTION('',(0.,0.,1.));
#802=VECTOR('',#801,1.);
#803=CARTESIAN_POINT('',(31.0857142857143,-2.28571428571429,28.));
#804=LINE('',#803,#802);
#805=CARTESIAN_POINT('',(31.0857142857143,-2.28571428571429,35.9));
#806=VERTEX_POINT('',#805);
#807=EDGE_CURVE('E204',#709,#806,#804,.T.);
#808=ORIENTED_EDGE('',*,*,#807,.F.);
#809=ORIENTED_EDGE('',*,*,#710,.F.);
#810=ORIENTED_EDGE('',*,*,#592,.T.);
#811=ORIENTED_EDGE('',*,*,#545,.F.);
#812=DIRECTION('',(-1.,0.,0.));
#813=VECTOR('',#812,1.);
#814=CARTESIAN_POINT('',(21.8024321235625,-2.28571428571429,38.));
#815=LINE('',#814,#813);
#816=CARTESIAN_POINT('',(23.4463291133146,-2.28571428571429,38.000000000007));
#817=VERTEX_POINT('',#816);
#818=EDGE_CURVE('E447',#817,#535,#815,.T.);
#819=ORIENTED_EDGE('',*,*,#818,.F.);
#820=CARTESIAN_POINT('',(23.7791576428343,-2.28571428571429,35.9000000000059));
#821=CARTESIAN_POINT('',(23.7232476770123,-2.28571428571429,36.2499304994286));
#822=CARTESIAN_POINT('',(23.6675569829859,-2.28571428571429,36.5998957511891));
#823=CARTESIAN_POINT('',(23.5566141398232,-2.28571428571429,37.2998957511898));
#824=CARTESIAN_POINT('',(23.5013619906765,-2.28571428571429,37.6499304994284));
#825=CARTESIAN_POINT('',(23.4463291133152,-2.28571428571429,38.0000000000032));
#826=B_SPLINE_CURVE_WITH_KNOTS('',3,(#820,#821,#822,#823,#824,#825),.UNSPECIFIED.,.F.,.F.,(4,2,
4),(0.,1.06310591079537,2.12621179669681),.UNSPECIFIED.);
#827=CARTESIAN_POINT('',(23.7791576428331,-2.28571428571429,35.9000000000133));
#828=VERTEX_POINT('',#827);
#829=EDGE_CURVE('E162',#828,#817,#826,.T.);
#830=ORIENTED_EDGE('',*,*,#829,.F.);
#831=DIRECTION('',(1.,0.,0.));
#832=VECTOR('',#831,1.);
#833=CARTESIAN_POINT('',(31.0857142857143,-2.28571428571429,35.9));
#834=LINE('',#833,#832);
#835=EDGE_CURVE('E206',#806,#828,#834,.F.);
#836=ORIENTED_EDGE('',*,*,#835,.F.);
#837=EDGE_LOOP('',(#808,#809,#810,#811,#819,#830,#836));
#838=FACE_BOUND('',#837,.T.);
#839=CARTESIAN_POINT('',(28.,-2.28571428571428,31.5675675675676));
#840=DIRECTION('',(0.,-1.,0.));
#841=DIRECTION('',(1.,0.,0.));
#842=AXIS2_PLACEMENT_3D('',#839,#840,#841);
#843=CIRCLE('',#842,1.6);
#844=CARTESIAN_POINT('',(29.6,-2.28571428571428,31.5675675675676));
#845=VERTEX_POINT('',#844);
#846=EDGE_CURVE('E159',#845,#845,#843,.F.);
#847=ORIENTED_EDGE('',*,*,#846,.F.);
#848=EDGE_LOOP('',(#847));
#849=FACE_BOUND('',#848,.T.);
#850=ADVANCED_FACE('F322',(#838,#849),#800,.F.);
#851=CARTESIAN_POINT('',(28.,7.60000000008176,31.5675675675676));
#852=DIRECTION('',(0.,-1.,0.));
#853=DIRECTION('',(1.,0.,0.));
#854=AXIS2_PLACEMENT_3D('',#851,#852,#853);
#855=CONICAL_SURFACE('',#854,1.59999999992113,0.785398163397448);
#856=CARTESIAN_POINT('',(28.,7.99999999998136,31.5675675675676));
#857=DIRECTION('',(0.,-1.,0.));
#858=DIRECTION('',(1.,0.,0.));
#859=AXIS2_PLACEMENT_3D('',#856,#857,#858);
#860=CIRCLE('',#859,1.20000000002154);
#861=CARTESIAN_POINT('',(29.2000000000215,7.99999999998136,31.5675675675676));
#862=VERTEX_POINT('',#861);
#863=EDGE_CURVE('E273',#862,#862,#860,.T.);
#864=ORIENTED_EDGE('',*,*,#863,.T.);
#865=EDGE_LOOP('',(#864));
#866=FACE_BOUND('',#865,.T.);
#867=ORIENTED_EDGE('',*,*,#407,.T.);
#868=EDGE_LOOP('',(#867));
#869=FACE_BOUND('',#868,.T.);
#870=ADVANCED_FACE('F390',(#866,#869),#855,.T.);
#871=CARTESIAN_POINT('',(21.8024321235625,0.,38.));
#872=DIRECTION('',(0.,0.,1.));
#873=DIRECTION('',(0.,1.,0.));
#874=AXIS2_PLACEMENT_3D('',#871,#872,#873);
#875=PLANE('',#874);
#876=ORIENTED_EDGE('',*,*,#763,.T.);
#877=CARTESIAN_POINT('',(28.,0.,38.0000000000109));
#878=DIRECTION('',(0.,0.,1.));
#879=DIRECTION('',(0.,1.,0.));
#880=AXIS2_PLACEMENT_3D('',#877,#878,#879);
#881=CIRCLE('',#880,5.09513575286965);
#882=EDGE_CURVE('E480',#754,#817,#881,.F.);
#883=ORIENTED_EDGE('',*,*,#882,.T.);
#884=ORIENTED_EDGE('',*,*,#818,.T.);
#885=ORIENTED_EDGE('',*,*,#536,.T.);
#886=ORIENTED_EDGE('',*,*,#489,.F.);
#887=ORIENTED_EDGE('',*,*,#444,.T.);
#888=EDGE_LOOP('',(#876,#883,#884,#885,#886,#887));
#889=FACE_BOUND('',#888,.T.);
#890=ADVANCED_FACE('F381',(#889),#875,.T.);
#891=CARTESIAN_POINT('',(28.,-7.60000000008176,31.5675675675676));
#892=DIRECTION('',(0.,1.,0.));
#893=DIRECTION('',(-1.,0.,0.));
#894=AXIS2_PLACEMENT_3D('',#891,#892,#893);
#895=CONICAL_SURFACE('',#894,1.59999999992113,0.785398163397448);
#896=ORIENTED_EDGE('',*,*,#673,.T.);
#897=EDGE_LOOP('',(#896));
#898=FACE_BOUND('',#897,.T.);
#899=CARTESIAN_POINT('',(28.,-7.99999999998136,31.5675675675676));
#900=DIRECTION('',(0.,1.,0.));
#901=DIRECTION('',(-1.,0.,0.));
#902=AXIS2_PLACEMENT_3D('',#899,#900,#901);
#903=CIRCLE('',#902,1.20000000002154);
#904=CARTESIAN_POINT('',(26.7999999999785,-7.99999999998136,31.5675675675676));
#905=VERTEX_POINT('',#904);
#906=EDGE_CURVE('E20',#905,#905,#903,.T.);
#907=ORIENTED_EDGE('',*,*,#906,.T.);
#908=EDGE_LOOP('',(#907));
#909=FACE_BOUND('',#908,.T.);
#910=ADVANCED_FACE('F375',(#898,#909),#895,.T.);
#911=CARTESIAN_POINT('',(31.0857142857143,1.37142857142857,28.));
#912=DIRECTION('',(0.,0.,-1.));
#913=DIRECTION('',(0.,-1.,0.));
#914=AXIS2_PLACEMENT_3D('',#911,#912,#913);
#915=CYLINDRICAL_SURFACE('',#914,0.914285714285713);
#916=ORIENTED_EDGE('',*,*,#774,.T.);
#917=ORIENTED_EDGE('',*,*,#695,.F.);
#918=DIRECTION('',(0.,0.,1.));
#919=VECTOR('',#918,1.);
#920=CARTESIAN_POINT('',(32.,1.37142857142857,28.));
#921=LINE('',#920,#919);
#922=CARTESIAN_POINT('',(32.,1.37142857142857,35.9));
#923=VERTEX_POINT('',#922);
#924=EDGE_CURVE('E211',#692,#923,#921,.T.);
#925=ORIENTED_EDGE('',*,*,#924,.T.);
#926=CARTESIAN_POINT('',(31.0857142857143,1.37142857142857,35.9));
#927=DIRECTION('',(0.,0.,-1.));
#928=DIRECTION('',(0.,-1.,0.));
#929=AXIS2_PLACEMENT_3D('',#926,#927,#928);
#930=CIRCLE('',#929,0.914285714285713);
#931=EDGE_CURVE('E147',#773,#923,#930,.T.);
#932=ORIENTED_EDGE('',*,*,#931,.F.);
#933=EDGE_LOOP('',(#916,#917,#925,#932));
#934=FACE_BOUND('',#933,.T.);
#935=ADVANCED_FACE('F145',(#934),#915,.F.);
#936=CARTESIAN_POINT('',(31.0857142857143,-1.37142857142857,28.));
#937=DIRECTION('',(0.,0.,-1.));
#938=DIRECTION('',(0.,-1.,0.));
#939=AXIS2_PLACEMENT_3D('',#936,#937,#938);
#940=CYLINDRICAL_SURFACE('',#939,0.914285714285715);
#941=DIRECTION('',(0.,0.,-1.));
#942=VECTOR('',#941,1.);
#943=CARTESIAN_POINT('',(32.,-1.37142857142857,28.));
#944=LINE('',#943,#942);
#945=CARTESIAN_POINT('',(32.,-1.37142857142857,35.9));
#946=VERTEX_POINT('',#945);
#947=EDGE_CURVE('E213',#718,#946,#944,.F.);
#948=ORIENTED_EDGE('',*,*,#947,.F.);
#949=ORIENTED_EDGE('',*,*,#719,.F.);
#950=ORIENTED_EDGE('',*,*,#807,.T.);
#951=CARTESIAN_POINT('',(31.0857142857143,-1.37142857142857,35.9));
#952=DIRECTION('',(0.,0.,-1.));
#953=DIRECTION('',(0.,-1.,0.));
#954=AXIS2_PLACEMENT_3D('',#951,#952,#953);
#955=CIRCLE('',#954,0.914285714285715);
#956=EDGE_CURVE('E200',#946,#806,#955,.T.);
#957=ORIENTED_EDGE('',*,*,#956,.F.);
#958=EDGE_LOOP('',(#948,#949,#950,#957));
#959=FACE_BOUND('',#958,.T.);
#960=ADVANCED_FACE('F388',(#959),#940,.F.);
#961=CARTESIAN_POINT('',(32.,1.37142857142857,28.));
#962=DIRECTION('',(1.,0.,0.));
#963=DIRECTION('',(0.,1.,0.));
#964=AXIS2_PLACEMENT_3D('',#961,#962,#963);
#965=PLANE('',#964);
#966=ORIENTED_EDGE('',*,*,#924,.F.);
#967=ORIENTED_EDGE('',*,*,#725,.F.);
#968=ORIENTED_EDGE('',*,*,#947,.T.);
#969=DIRECTION('',(0.,1.,0.));
#970=VECTOR('',#969,1.);
#971=CARTESIAN_POINT('',(32.,0.,35.9));
#972=LINE('',#971,#970);
#973=EDGE_CURVE('E201',#923,#946,#972,.F.);
#974=ORIENTED_EDGE('',*,*,#973,.F.);
#975=EDGE_LOOP('',(#966,#967,#968,#974));
#976=FACE_BOUND('',#975,.T.);
#977=ADVANCED_FACE('F405',(#976),#965,.F.);
#978=CARTESIAN_POINT('',(28.,0.,28.00000000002));
#979=DIRECTION('',(0.,0.,1.));
#980=DIRECTION('',(0.,1.,0.));
#981=AXIS2_PLACEMENT_3D('',#978,#979,#980);
#982=CONICAL_SURFACE('',#981,2.00000000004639,0.785398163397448);
#983=ORIENTED_EDGE('',*,*,#736,.F.);
#984=EDGE_LOOP('',(#983));
#985=FACE_BOUND('',#984,.T.);
#986=ORIENTED_EDGE('',*,*,#62,.F.);
#987=EDGE_LOOP('',(#986));
#988=FACE_BOUND('',#987,.T.);
#989=ADVANCED_FACE('F294',(#985,#988),#982,.F.);
#990=CARTESIAN_POINT('',(28.,0.,37.999999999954));
#991=DIRECTION('',(0.,0.,1.));
#992=DIRECTION('',(0.,1.,0.));
#993=AXIS2_PLACEMENT_3D('',#990,#991,#992);
#994=CONICAL_SURFACE('',#993,5.09513575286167,0.139626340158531);
#995=CARTESIAN_POINT('',(28.,0.,35.9000000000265));
#996=DIRECTION('',(0.,0.,1.));
#997=DIRECTION('',(0.,1.,0.));
#998=AXIS2_PLACEMENT_3D('',#995,#996,#997);
#999=CIRCLE('',#998,4.79999999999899);
#1000=EDGE_CURVE('E227',#828,#756,#999,.T.);
#1001=ORIENTED_EDGE('',*,*,#1000,.F.);
#1002=ORIENTED_EDGE('',*,*,#829,.T.);
#1003=ORIENTED_EDGE('',*,*,#882,.F.);
#1004=ORIENTED_EDGE('',*,*,#757,.T.);
#1005=EDGE_LOOP('',(#1001,#1002,#1003,#1004));
#1006=FACE_BOUND('',#1005,.T.);
#1007=ADVANCED_FACE('F290',(#1006),#994,.F.);
#1008=CARTESIAN_POINT('',(25.6,0.,35.9));
#1009=DIRECTION('',(0.,0.,1.));
#1010=DIRECTION('',(0.,1.,0.));
#1011=AXIS2_PLACEMENT_3D('',#1008,#1009,#1010);
#1012=PLANE('',#1011);
#1013=ORIENTED_EDGE('',*,*,#973,.T.);
#1014=ORIENTED_EDGE('',*,*,#956,.T.);
#1015=ORIENTED_EDGE('',*,*,#835,.T.);
#1016=ORIENTED_EDGE('',*,*,#1000,.T.);
#1017=ORIENTED_EDGE('',*,*,#780,.T.);
#1018=ORIENTED_EDGE('',*,*,#931,.T.);
#1019=EDGE_LOOP('',(#1013,#1014,#1015,#1016,#1017,#1018));
#1020=FACE_BOUND('',#1019,.T.);
#1021=ADVANCED_FACE('F293',(#1020),#1012,.T.);
#1022=CARTESIAN_POINT('',(28.,0.,31.5675675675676));
#1023=DIRECTION('',(0.,-1.,0.));
#1024=DIRECTION('',(1.,0.,0.));
#1025=AXIS2_PLACEMENT_3D('',#1022,#1023,#1024);
#1026=CYLINDRICAL_SURFACE('',#1025,1.6);
#1027=ORIENTED_EDGE('',*,*,#846,.T.);
#1028=EDGE_LOOP('',(#1027));
#1029=FACE_BOUND('',#1028,.T.);
#1030=ORIENTED_EDGE('',*,*,#791,.T.);
#1031=EDGE_LOOP('',(#1030));
#1032=FACE_BOUND('',#1031,.T.);
#1033=ADVANCED_FACE('F288',(#1029,#1032),#1026,.T.);
#1034=CARTESIAN_POINT('',(28.,8.,32.1675675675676));
#1035=DIRECTION('',(0.,1.,0.));
#1036=DIRECTION('',(-1.,0.,0.));
#1037=AXIS2_PLACEMENT_3D('',#1034,#1035,#1036);
#1038=PLANE('',#1037);
#1039=ORIENTED_EDGE('',*,*,#863,.F.);
#1040=EDGE_LOOP('',(#1039));
#1041=FACE_BOUND('',#1040,.T.);
#1042=ADVANCED_FACE('F284',(#1041),#1038,.T.);
#1043=CARTESIAN_POINT('',(28.,-8.,32.1675675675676));
#1044=DIRECTION('',(0.,-1.,0.));
#1045=DIRECTION('',(1.,0.,0.));
#1046=AXIS2_PLACEMENT_3D('',#1043,#1044,#1045);
#1047=PLANE('',#1046);
#1048=ORIENTED_EDGE('',*,*,#906,.F.);
#1049=EDGE_LOOP('',(#1048));
#1050=FACE_BOUND('',#1049,.T.);
#1051=ADVANCED_FACE('F18',(#1050),#1047,.T.);
#1052=CARTESIAN_POINT('',(0.,0.,24.));
#1053=DIRECTION('',(0.,0.,1.));
#1054=DIRECTION('',(0.,1.,0.));
#1055=AXIS2_PLACEMENT_3D('',#1052,#1053,#1054);
#1056=PLANE('',#1055);
#1057=ORIENTED_EDGE('',*,*,#31,.T.);
#1058=EDGE_LOOP('',(#1057));
#1059=FACE_BOUND('',#1058,.T.);
#1060=ADVANCED_FACE('F352',(#1059),#1056,.T.);
#1061=CARTESIAN_POINT('',(-25.54,0.,24.));
#1062=DIRECTION('',(0.,0.,1.));
#1063=DIRECTION('',(0.,1.,0.));
#1064=AXIS2_PLACEMENT_3D('',#1061,#1062,#1063);
#1065=CIRCLE('',#1064,10.27);
#1066=CARTESIAN_POINT('',(-25.0335973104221,10.2575073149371,24.));
#1067=VERTEX_POINT('',#1066);
#1068=CARTESIAN_POINT('',(-25.0335973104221,-10.2575073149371,24.));
#1069=VERTEX_POINT('',#1068);
#1070=EDGE_CURVE('E667',#1067,#1069,#1065,.T.);
#1071=ORIENTED_EDGE('',*,*,#1070,.T.);
#1072=DIRECTION('',(0.998783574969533,0.0493089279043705,0.));
#1073=VECTOR('',#1072,1.);
#1074=CARTESIAN_POINT('',(-25.0335973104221,-10.2575073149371,24.));
#1075=LINE('',#1074,#1073);
#1076=CARTESIAN_POINT('',(25.5725080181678,-7.7591354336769,24.));
#1077=VERTEX_POINT('',#1076);
#1078=EDGE_CURVE('E783',#1069,#1077,#1075,.T.);
#1079=ORIENTED_EDGE('',*,*,#1078,.T.);
#1080=CARTESIAN_POINT('',(28.,0.,24.));
#1081=DIRECTION('',(0.,0.,-1.));
#1082=DIRECTION('',(0.,-1.,0.));
#1083=AXIS2_PLACEMENT_3D('',#1080,#1081,#1082);
#1084=CIRCLE('',#1083,8.13);
#1085=CARTESIAN_POINT('',(25.5725080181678,7.7591354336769,24.));
#1086=VERTEX_POINT('',#1085);
#1087=EDGE_CURVE('E661',#1077,#1086,#1084,.F.);
#1088=ORIENTED_EDGE('',*,*,#1087,.T.);
#1089=DIRECTION('',(-0.998783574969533,0.0493089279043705,0.));
#1090=VECTOR('',#1089,1.);
#1091=CARTESIAN_POINT('',(28.3762271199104,7.62071867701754,24.));
#1092=LINE('',#1091,#1090);
#1093=EDGE_CURVE('E669',#1086,#1067,#1092,.T.);
#1094=ORIENTED_EDGE('',*,*,#1093,.T.);
#1095=EDGE_LOOP('',(#1071,#1079,#1088,#1094));
#1096=FACE_BOUND('',#1095,.T.);
#1097=ORIENTED_EDGE('',*,*,#237,.F.);
#1098=ORIENTED_EDGE('',*,*,#584,.T.);
#1099=ORIENTED_EDGE('',*,*,#295,.F.);
#1100=ORIENTED_EDGE('',*,*,#638,.T.);
#1101=ORIENTED_EDGE('',*,*,#266,.F.);
#1102=ORIENTED_EDGE('',*,*,#613,.T.);
#1103=EDGE_LOOP('',(#1097,#1098,#1099,#1100,#1101,#1102));
#1104=FACE_BOUND('',#1103,.T.);
#1105=ADVANCED_FACE('F353',(#1096,#1104),#1056,.T.);
#1106=CARTESIAN_POINT('',(-25.54,0.,54.));
#1107=DIRECTION('',(0.,0.,1.));
#1108=DIRECTION('',(0.,1.,0.));
#1109=AXIS2_PLACEMENT_3D('',#1106,#1107,#1108);
#1110=CYLINDRICAL_SURFACE('',#1109,10.27);
#1111=ORIENTED_EDGE('',*,*,#1070,.F.);
#1112=DIRECTION('',(0.,0.,1.));
#1113=VECTOR('',#1112,1.);
#1114=CARTESIAN_POINT('',(-25.0335973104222,10.2575073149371,54.));
#1115=LINE('',#1114,#1113);
#1116=CARTESIAN_POINT('',(-25.0335973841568,10.2575073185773,36.0463788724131));
#1117=VERTEX_POINT('',#1116);
#1118=EDGE_CURVE('E666',#1067,#1117,#1115,.T.);
#1119=ORIENTED_EDGE('',*,*,#1118,.T.);
#1120=CARTESIAN_POINT('',(-25.0335973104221,-10.2575073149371,36.0463788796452));
#1121=CARTESIAN_POINT('',(-25.2021120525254,-10.2658277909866,36.0298502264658));
#1122=CARTESIAN_POINT('',(-25.3708246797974,-10.269992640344,36.0134483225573));
#1123=CARTESIAN_POINT('',(-25.7085496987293,-10.270007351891,35.9808930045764));
#1124=CARTESIAN_POINT('',(-25.8775621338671,-10.2658437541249,35.964740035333));
#1125=CARTESIAN_POINT('',(-26.3348096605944,-10.2432673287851,35.9213974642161));
#1126=CARTESIAN_POINT('',(-26.6227151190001,-10.2168517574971,35.8944927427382));
#1127=CARTESIAN_POINT('',(-27.1954784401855,-10.1398153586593,35.8416650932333));
#1128=CARTESIAN_POINT('',(-27.4803346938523,-10.089182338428,35.815742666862));
#1129=CARTESIAN_POINT('',(-28.045242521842,-9.96395814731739,35.7649600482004));
#1130=CARTESIAN_POINT('',(-28.3252871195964,-9.8893348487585,35.7401013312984));
#1131=CARTESIAN_POINT('',(-28.8781630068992,-9.71665807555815,35.6915794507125));
#1132=CARTESIAN_POINT('',(-29.1509942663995,-9.61860450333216,35.6679162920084));
#1133=CARTESIAN_POINT('',(-29.6873559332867,-9.39979716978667,35.6218834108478));
#1134=CARTESIAN_POINT('',(-29.9508907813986,-9.27905442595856,35.599513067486));
#1135=CARTESIAN_POINT('',(-30.4669102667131,-9.01567354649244,35.5561318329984));
#1136=CARTESIAN_POINT('',(-30.7193945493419,-8.8730347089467,35.5351209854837));
#1137=CARTESIAN_POINT('',(-31.2113825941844,-8.56692616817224,35.494539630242));
#1138=CARTESIAN_POINT('',(-31.4508915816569,-8.40346494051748,35.4749685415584));
#1139=CARTESIAN_POINT('',(-31.9153059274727,-8.05681910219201,35.437322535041));
#1140=CARTESIAN_POINT('',(-32.1402114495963,-7.87363471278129,35.4192476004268));
#1141=CARTESIAN_POINT('',(-32.5732467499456,-7.48932131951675,35.3846958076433));
#1142=CARTESIAN_POINT('',(-32.7814172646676,-7.28823856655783,35.3682150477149));
#1143=CARTESIAN_POINT('',(-33.1801064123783,-6.86915713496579,35.3368522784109));
#1144=CARTESIAN_POINT('',(-33.3706249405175,-6.65115835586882,35.3219702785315));
#1145=CARTESIAN_POINT('',(-33.7326986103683,-6.19970552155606,35.2938459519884));
#1146=CARTESIAN_POINT('',(-33.9042464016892,-5.96624553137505,35.2806042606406));
#1147=CARTESIAN_POINT('',(-34.2270443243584,-5.48561390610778,35.2558080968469));
#1148=CARTESIAN_POINT('',(-34.3782949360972,-5.23844259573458,35.2442535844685));
#1149=CARTESIAN_POINT('',(-34.6590548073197,-4.73277551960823,35.222892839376));
#1150=CARTESIAN_POINT('',(-34.788616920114,-4.47430927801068,35.2130823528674));
#1151=CARTESIAN_POINT('',(-35.0255139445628,-3.94732599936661,35.1952039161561));
#1152=CARTESIAN_POINT('',(-35.1328489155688,-3.67880898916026,35.1871359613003));
#1153=CARTESIAN_POINT('',(-35.3243761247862,-3.13402815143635,35.1727766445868));
#1154=CARTESIAN_POINT('',(-35.408601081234,-2.85777589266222,35.1664827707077));
#1155=CARTESIAN_POINT('',(-35.5534742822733,-2.29922704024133,35.1556766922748));
#1156=CARTESIAN_POINT('',(-35.614130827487,-2.01693261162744,35.1511638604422));
#1157=CARTESIAN_POINT('',(-35.7117465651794,-1.44659900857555,35.1439092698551));
#1158=CARTESIAN_POINT('',(-35.7485690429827,-1.15853629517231,35.1411777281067));
#1159=CARTESIAN_POINT('',(-35.7976957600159,-0.580315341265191,35.1375347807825));
#1160=CARTESIAN_POINT('',(-35.8099999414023,-0.290157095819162,35.1366233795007));
#1161=CARTESIAN_POINT('',(-35.8100000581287,0.287834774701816,35.1366233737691));
#1162=CARTESIAN_POINT('',(-35.7978921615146,0.575668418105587,35.1375202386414));
#1163=CARTESIAN_POINT('',(-35.7495396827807,1.14939207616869,35.1411057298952));
#1164=CARTESIAN_POINT('',(-35.7132866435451,1.43528137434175,35.143794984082));
#1165=CARTESIAN_POINT('',(-35.6168300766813,2.00337722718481,35.1509630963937));
#1166=CARTESIAN_POINT('',(-35.5565933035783,2.28557810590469,35.155444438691));
#1167=CARTESIAN_POINT('',(-35.4126058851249,2.84388147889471,35.1661836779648));
#1168=CARTESIAN_POINT('',(-35.3288552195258,3.11998396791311,35.1724415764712));
#1169=CARTESIAN_POINT('',(-35.1385121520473,3.66393720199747,35.1867106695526));
#1170=CARTESIAN_POINT('',(-35.0319356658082,3.93179354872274,35.1947206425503));
#1171=CARTESIAN_POINT('',(-34.7966731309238,4.45756090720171,35.2124730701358));
#1172=CARTESIAN_POINT('',(-34.6679866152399,4.71547170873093,35.2222155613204));
#1173=CARTESIAN_POINT('',(-34.3894752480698,5.21943971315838,35.2434008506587));
#1174=CARTESIAN_POINT('',(-34.2396568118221,5.46550048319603,35.2548431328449));
#1175=CARTESIAN_POINT('',(-33.9199304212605,5.94411388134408,35.279395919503));
#1176=CARTESIAN_POINT('',(-33.7500225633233,6.17666657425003,35.2925064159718));
#1177=CARTESIAN_POINT('',(-33.3911231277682,6.62689539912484,35.3203725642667));
#1178=CARTESIAN_POINT('',(-33.2021091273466,6.84455353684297,35.3351301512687));
#1179=CARTESIAN_POINT('',(-32.8065223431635,7.26315933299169,35.3662324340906));
#1180=CARTESIAN_POINT('',(-32.5999494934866,7.46410692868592,35.3825771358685));
#1181=CARTESIAN_POINT('',(-32.1707242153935,7.84788358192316,35.416802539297));
#1182=CARTESIAN_POINT('',(-31.9480716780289,8.03071251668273,35.4346832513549));
#1183=CARTESIAN_POINT('',(-31.4882816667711,8.3769726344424,35.4719232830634));
#1184=CARTESIAN_POINT('',(-31.2511442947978,8.5404039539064,35.4912825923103));
#1185=CARTESIAN_POINT('',(-30.763428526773,8.84714095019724,35.5314697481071));
#1186=CARTESIAN_POINT('',(-30.5128161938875,8.99039217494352,35.5523013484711));
#1187=CARTESIAN_POINT('',(-30.0005187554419,9.25525913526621,35.5953170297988));
#1188=CARTESIAN_POINT('',(-29.7388336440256,9.37687485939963,35.6175011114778));
#1189=CARTESIAN_POINT('',(-29.2062775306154,9.59762450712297,35.6631424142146));
#1190=CARTESIAN_POINT('',(-28.9354070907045,9.69675980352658,35.6865995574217));
#1191=CARTESIAN_POINT('',(-28.3864088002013,9.87187158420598,35.7347017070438));
#1192=CARTESIAN_POINT('',(-28.1082819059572,9.9478511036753,35.7593465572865));
#1193=CARTESIAN_POINT('',(-27.5987261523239,10.0642759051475,35.8050663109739));
#1194=CARTESIAN_POINT('',(-27.3681792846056,10.1086949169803,35.8259579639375));
#1195=CARTESIAN_POINT('',(-26.9046670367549,10.1816311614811,35.868412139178));
#1196=CARTESIAN_POINT('',(-26.671701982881,10.2101505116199,35.8899745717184));
#1197=CARTESIAN_POINT('',(-26.2046203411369,10.2511501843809,35.9336949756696));
#1198=CARTESIAN_POINT('',(-25.970504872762,10.2636438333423,35.9558524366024));
#1199=CARTESIAN_POINT('',(-25.5019860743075,10.2726058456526,36.0007188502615));
#1200=CARTESIAN_POINT('',(-25.2675827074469,10.2690718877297,36.0234278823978));
#1201=CARTESIAN_POINT('',(-25.0335974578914,10.2575073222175,36.046378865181));
#1202=B_SPLINE_CURVE_WITH_KNOTS('',3,(#1120,#1121,#1122,#1123,#1124,#1125,#1126,#1127,#1128,
#1129,#1130,#1131,#1132,#1133,#1134,#1135,#1136,#1137,#1138,#1139,#1140,#1141,#1142,#1143,#1144,
#1145,#1146,#1147,#1148,#1149,#1150,#1151,#1152,#1153,#1154,#1155,#1156,#1157,#1158,#1159,#1160,
#1161,#1162,#1163,#1164,#1165,#1166,#1167,#1168,#1169,#1170,#1171,#1172,#1173,#1174,#1175,#1176,
#1177,#1178,#1179,#1180,#1181,#1182,#1183,#1184,#1185,#1186,#1187,#1188,#1189,#1190,#1191,#1192,
#1193,#1194,#1195,#1196,#1197,#1198,#1199,#1200,#1201),.UNSPECIFIED.,.F.,.F.,(4,2,2,2,2,2,2,2,2,
2,2,2,2,2,2,2,2,2,2,2,2,2,2,2,2,2,2,2,2,2,2,2,2,2,2,2,2,2,2,2,4),(0.,0.508492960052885,
1.01780838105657,1.88780147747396,2.7582330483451,3.62983518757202,4.5014409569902,
5.37262457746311,6.24383613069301,7.11469419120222,7.98554248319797,8.85420236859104,
9.72286741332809,10.5918678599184,11.4608477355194,12.3276781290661,13.1945062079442,
14.0601006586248,14.9253899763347,15.795599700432,16.665811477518,17.5290583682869,
18.392607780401,19.2573584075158,20.1221097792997,20.9862601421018,21.8504287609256,
22.7143355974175,23.5782382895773,24.4431668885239,25.3080987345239,26.1730364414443,
27.0379680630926,27.9051905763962,28.7724135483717,29.6395835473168,30.5066398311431,
31.2132562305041,31.919778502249,32.6257128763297,33.3317494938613),.UNSPECIFIED.);
#1203=CARTESIAN_POINT('',(-25.0335973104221,-10.2575073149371,36.0463788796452));
#1204=VERTEX_POINT('',#1203);
#1205=EDGE_CURVE('E643',#1204,#1117,#1202,.T.);
#1206=ORIENTED_EDGE('',*,*,#1205,.F.);
#1207=DIRECTION('',(0.,0.,1.));
#1208=VECTOR('',#1207,1.);
#1209=CARTESIAN_POINT('',(-25.0335973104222,-10.2575073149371,54.));
#1210=LINE('',#1209,#1208);
#1211=EDGE_CURVE('E674',#1204,#1069,#1210,.F.);
#1212=ORIENTED_EDGE('',*,*,#1211,.T.);
#1213=EDGE_LOOP('',(#1111,#1119,#1206,#1212));
#1214=FACE_BOUND('',#1213,.T.);
#1215=ADVANCED_FACE('F362',(#1214),#1110,.F.);
#1216=CARTESIAN_POINT('',(-25.0335973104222,-10.2575073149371,54.));
#1217=DIRECTION('',(0.0493089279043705,-0.998783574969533,0.));
#1218=DIRECTION('',(0.998783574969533,0.0493089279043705,0.));
#1219=AXIS2_PLACEMENT_3D('',#1216,#1217,#1218);
#1220=PLANE('',#1219);
#1221=ORIENTED_EDGE('',*,*,#1078,.F.);
#1222=ORIENTED_EDGE('',*,*,#1211,.F.);
#1223=CARTESIAN_POINT('',(25.5725081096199,-7.75913542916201,36.0806521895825));
#1224=CARTESIAN_POINT('',(25.0473226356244,-7.78506330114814,36.1320821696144));
#1225=CARTESIAN_POINT('',(24.5221198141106,-7.81099202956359,36.1833349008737));
#1226=CARTESIAN_POINT('',(23.4716720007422,-7.86285156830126,36.2854080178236));
#1227=CARTESIAN_POINT('',(22.9464270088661,-7.88878237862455,36.3362284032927));
#1228=CARTESIAN_POINT('',(21.3705966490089,-7.96657951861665,36.4879262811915));
#1229=CARTESIAN_POINT('',(20.3199376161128,-8.0184494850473,36.5880383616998));
#1230=CARTESIAN_POINT('',(18.2154924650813,-8.12234379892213,36.7855474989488));
#1231=CARTESIAN_POINT('',(17.161705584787,-8.17436818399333,36.8829364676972));
#1232=CARTESIAN_POINT('',(15.5807158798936,-8.25242003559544,37.0255249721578));
#1233=CARTESIAN_POINT('',(15.0536704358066,-8.27843973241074,37.0724717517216));
#1234=CARTESIAN_POINT('',(13.9994497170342,-8.33048553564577,37.1648781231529));
#1235=CARTESIAN_POINT('',(13.4722744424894,-8.35651164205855,37.2103377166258));
#1236=CARTESIAN_POINT('',(12.4209146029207,-8.4084162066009,37.2990941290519));
#1237=CARTESIAN_POINT('',(11.8967309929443,-8.43429461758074,37.3424022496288));
#1238=CARTESIAN_POINT('',(10.8481689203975,-8.48606105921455,37.4266004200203));
#1239=CARTESIAN_POINT('',(10.3237904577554,-8.51194908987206,37.4674904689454));
#1240=CARTESIAN_POINT('',(9.27476184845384,-8.56373856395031,37.546131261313));
#1241=CARTESIAN_POINT('',(8.7501116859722,-8.58964000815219,37.5838817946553));
#1242=CARTESIAN_POINT('',(7.70052985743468,-8.6414567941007,37.6552892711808));
#1243=CARTESIAN_POINT('',(7.17559819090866,-8.66737213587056,37.6889462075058));
#1244=CARTESIAN_POINT('',(6.12622073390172,-8.71917883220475,37.7509151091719));
#1245=CARTESIAN_POINT('',(5.60177542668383,-8.74507016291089,37.7792351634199));
#1246=CARTESIAN_POINT('',(4.55256251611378,-8.79686873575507,37.8291859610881));
#1247=CARTESIAN_POINT('',(4.02779491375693,-8.82277597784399,37.850816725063));
#1248=CARTESIAN_POINT('',(2.97807374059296,-8.8745996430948,37.8859483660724));
#1249=CARTESIAN_POINT('',(2.45312021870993,-8.90051606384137,37.8994506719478));
#1250=CARTESIAN_POINT('',(1.40305717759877,-8.95235660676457,37.9172155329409));
#1251=CARTESIAN_POINT('',(0.877947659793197,-8.97828072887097,37.9214781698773));
#1252=CARTESIAN_POINT('',(-0.175736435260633,-9.03030003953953,37.9203643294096));
#1253=CARTESIAN_POINT('',(-0.704310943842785,-9.05639522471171,37.91492386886));
#1254=CARTESIAN_POINT('',(-1.76128388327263,-9.10857690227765,37.8947862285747));
#1255=CARTESIAN_POINT('',(-2.28968231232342,-9.13466339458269,37.8800889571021));
#1256=CARTESIAN_POINT('',(-3.34628267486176,-9.18682667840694,37.842637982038));
#1257=CARTESIAN_POINT('',(-3.87448455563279,-9.21290346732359,37.8198828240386));
#1258=CARTESIAN_POINT('',(-4.93055980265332,-9.26504082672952,37.7677959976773));
#1259=CARTESIAN_POINT('',(-5.45843316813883,-9.29110139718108,37.7384643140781));
#1260=CARTESIAN_POINT('',(-6.51468165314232,-9.3432473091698,37.6745885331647));
#1261=CARTESIAN_POINT('',(-7.04305628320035,-9.36933262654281,37.6400364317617));
#1262=CARTESIAN_POINT('',(-8.09952673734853,-9.42148949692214,37.5669437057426));
#1263=CARTESIAN_POINT('',(-8.62762256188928,-9.44756104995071,37.5284030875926));
#1264=CARTESIAN_POINT('',(-9.68354342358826,-9.49969078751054,37.4482702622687));
#1265=CARTESIAN_POINT('',(-10.2113684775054,-9.52574897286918,37.4066782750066));
#1266=CARTESIAN_POINT('',(-11.2668271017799,-9.57785589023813,37.3211399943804));
#1267=CARTESIAN_POINT('',(-11.7944606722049,-9.60390462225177,37.277193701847));
#1268=CARTESIAN_POINT('',(-13.3835278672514,-9.68235525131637,37.1421062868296));
#1269=CARTESIAN_POINT('',(-14.4447278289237,-9.73474561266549,37.0482165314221));
#1270=CARTESIAN_POINT('',(-16.5667331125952,-9.83950685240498,36.8559537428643));
#1271=CARTESIAN_POINT('',(-17.6275384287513,-9.89187773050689,36.7575806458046));
#1272=CARTESIAN_POINT('',(-19.7460047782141,-9.99646425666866,36.5581706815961));
#1273=CARTESIAN_POINT('',(-20.8036665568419,-10.0486799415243,36.4571417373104));
#1274=CARTESIAN_POINT('',(-22.3900032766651,-10.1269957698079,36.3041096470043));
#1275=CARTESIAN_POINT('',(-22.9187502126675,-10.1530994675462,36.2528514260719));
#1276=CARTESIAN_POINT('',(-23.9762028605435,-10.2053048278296,36.1499130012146));
#1277=CARTESIAN_POINT('',(-24.5049085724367,-10.2314064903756,36.098232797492));
#1278=CARTESIAN_POINT('',(-25.0335973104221,-10.2575073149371,36.0463788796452));
#1279=B_SPLINE_CURVE_WITH_KNOTS('',3,(#1223,#1224,#1225,#1226,#1227,#1228,#1229,#1230,#1231,
#1232,#1233,#1234,#1235,#1236,#1237,#1238,#1239,#1240,#1241,#1242,#1243,#1244,#1245,#1246,#1247,
#1248,#1249,#1250,#1251,#1252,#1253,#1254,#1255,#1256,#1257,#1258,#1259,#1260,#1261,#1262,#1263,
#1264,#1265,#1266,#1267,#1268,#1269,#1270,#1271,#1272,#1273,#1274,#1275,#1276,#1277,#1278),
.UNSPECIFIED.,.F.,.F.,(4,2,2,2,2,2,2,2,2,2,2,2,2,2,2,2,2,2,2,2,2,2,2,2,2,2,2,4),(0.,
1.5850027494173,3.17000631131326,6.34007898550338,9.51873773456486,11.1080509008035,
12.6973623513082,14.2771757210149,15.856989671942,17.4369092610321,19.0168314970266,
20.5943394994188,22.1718426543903,23.7490684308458,25.3262802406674,26.9139308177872,
28.5015971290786,30.0895501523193,31.6775068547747,33.267923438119,34.8583374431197,
36.4486369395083,38.0389358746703,41.2388154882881,44.4387407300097,47.6300126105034,
49.225612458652,50.821211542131),.UNSPECIFIED.);
#1280=CARTESIAN_POINT('',(25.5725080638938,-7.75913543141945,36.0806521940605));
#1281=VERTEX_POINT('',#1280);
#1282=EDGE_CURVE('E618',#1281,#1204,#1279,.T.);
#1283=ORIENTED_EDGE('',*,*,#1282,.F.);
#1284=DIRECTION('',(0.,0.,1.));
#1285=VECTOR('',#1284,1.);
#1286=CARTESIAN_POINT('',(25.5725080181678,-7.7591354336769,54.));
#1287=LINE('',#1286,#1285);
#1288=EDGE_CURVE('E670',#1077,#1281,#1287,.T.);
#1289=ORIENTED_EDGE('',*,*,#1288,.F.);
#1290=EDGE_LOOP('',(#1221,#1222,#1283,#1289));
#1291=FACE_BOUND('',#1290,.T.);
#1292=ADVANCED_FACE('F368',(#1291),#1220,.F.);
#1293=CARTESIAN_POINT('',(28.,0.,24.));
#1294=DIRECTION('',(0.,0.,-1.));
#1295=DIRECTION('',(0.,-1.,0.));
#1296=AXIS2_PLACEMENT_3D('',#1293,#1294,#1295);
#1297=CYLINDRICAL_SURFACE('',#1296,8.13);
#1298=CARTESIAN_POINT('',(25.5725080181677,7.75913543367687,36.0806521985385));
#1299=CARTESIAN_POINT('',(25.7916465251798,7.82771942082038,36.0567943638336));
#1300=CARTESIAN_POINT('',(26.0137002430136,7.88697320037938,36.0329323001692));
#1301=CARTESIAN_POINT('',(26.4620283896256,7.98649873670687,35.9853550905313));
#1302=CARTESIAN_POINT('',(26.6883026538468,8.02677123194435,35.9616399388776));
#1303=CARTESIAN_POINT('',(27.1433481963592,8.08800031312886,35.9145236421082));
#1304=CARTESIAN_POINT('',(27.3721179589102,8.1089680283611,35.8911223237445));
#1305=CARTESIAN_POINT('',(27.8306523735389,8.13147608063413,35.844759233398));
#1306=CARTESIAN_POINT('',(28.0604170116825,8.13301668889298,35.8217974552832));
#1307=CARTESIAN_POINT('',(28.5194248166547,8.11664126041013,35.776430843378));
#1308=CARTESIAN_POINT('',(28.7486676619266,8.09871540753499,35.7540262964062));
#1309=CARTESIAN_POINT('',(29.204880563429,8.04350405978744,35.7099048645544));
#1310=CARTESIAN_POINT('',(29.4318505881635,8.00621829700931,35.6881879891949));
#1311=CARTESIAN_POINT('',(29.8818373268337,7.91254649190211,35.6455566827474));
#1312=CARTESIAN_POINT('',(30.1048549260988,7.85616478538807,35.6246420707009));
#1313=CARTESIAN_POINT('',(30.5453864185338,7.72468421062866,35.5837109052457));
#1314=CARTESIAN_POINT('',(30.762900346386,7.64958546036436,35.5636943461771));
#1315=CARTESIAN_POINT('',(31.1904310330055,7.48135785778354,35.5246905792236));
#1316=CARTESIAN_POINT('',(31.400461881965,7.38826527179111,35.5057013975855));
#1317=CARTESIAN_POINT('',(31.812036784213,7.18456777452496,35.4687875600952));
#1318=CARTESIAN_POINT('',(32.0135780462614,7.07395715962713,35.4508632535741));
#1319=CARTESIAN_POINT('',(32.4066300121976,6.83602832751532,35.4161640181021));
#1320=CARTESIAN_POINT('',(32.5981414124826,6.70871127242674,35.3993890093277));
#1321=CARTESIAN_POINT('',(32.9697593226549,6.43826083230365,35.3670569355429));
#1322=CARTESIAN_POINT('',(33.149865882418,6.2951275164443,35.3514998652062));
#1323=CARTESIAN_POINT('',(33.4967191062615,5.99461734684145,35.321722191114));
#1324=CARTESIAN_POINT('',(33.6635128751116,5.83729533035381,35.3074968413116));
#1325=CARTESIAN_POINT('',(33.9832193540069,5.50912385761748,35.2803782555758));
#1326=CARTESIAN_POINT('',(34.1361366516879,5.33827890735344,35.2674845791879));
#1327=CARTESIAN_POINT('',(34.4271017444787,4.98415496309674,35.2430688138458));
#1328=CARTESIAN_POINT('',(34.5651434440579,4.80087092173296,35.2315472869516));
#1329=CARTESIAN_POINT('',(34.8252775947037,4.42324011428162,35.2099259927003));
#1330=CARTESIAN_POINT('',(34.9473703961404,4.22889359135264,35.19982619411));
#1331=CARTESIAN_POINT('',(35.1743788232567,3.83111878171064,35.1811139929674));
#1332=CARTESIAN_POINT('',(35.2793447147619,3.62771938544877,35.1724972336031));
#1333=CARTESIAN_POINT('',(35.4717752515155,3.212752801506,35.1567462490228));
#1334=CARTESIAN_POINT('',(35.5592402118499,3.00118576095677,35.1496119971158));
#1335=CARTESIAN_POINT('',(35.7159321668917,2.57166888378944,35.1368601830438));
#1336=CARTESIAN_POINT('',(35.7851827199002,2.35372770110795,35.1312406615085));
#1337=CARTESIAN_POINT('',(35.9050710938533,1.91283241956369,35.1215280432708));
#1338=CARTESIAN_POINT('',(35.9557150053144,1.689879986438,35.1174344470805));
#1339=CARTESIAN_POINT('',(36.0411306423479,1.22367789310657,35.110537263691));
#1340=CARTESIAN_POINT('',(36.0744340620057,0.980156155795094,35.1078528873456));
#1341=CARTESIAN_POINT('',(36.1188684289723,0.491086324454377,35.104272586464));
#1342=CARTESIAN_POINT('',(36.1299995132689,0.24553824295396,35.1033766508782));
#1343=CARTESIAN_POINT('',(36.1300004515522,-0.227791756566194,35.1033765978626));
#1344=CARTESIAN_POINT('',(36.1204211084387,-0.455575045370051,35.1041476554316));
#1345=CARTESIAN_POINT('',(36.0821680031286,-0.909601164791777,35.1072295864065));
#1346=CARTESIAN_POINT('',(36.053488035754,-1.13584347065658,35.1095409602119));
#1347=CARTESIAN_POINT('',(35.9771848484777,-1.58539282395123,35.1156998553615));
#1348=CARTESIAN_POINT('',(35.9295369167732,-1.80869564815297,35.1195493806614));
#1349=CARTESIAN_POINT('',(35.8156434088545,-2.25047871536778,35.1287708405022));
#1350=CARTESIAN_POINT('',(35.7493975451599,-2.46895888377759,35.1341427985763));
#1351=CARTESIAN_POINT('',(35.598838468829,-2.8993975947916,35.146385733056));
#1352=CARTESIAN_POINT('',(35.5145371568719,-3.1113603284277,35.1532557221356));
#1353=CARTESIAN_POINT('',(35.3284494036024,-3.52741591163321,35.1684720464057));
#1354=CARTESIAN_POINT('',(35.2266626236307,-3.73150860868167,35.1768184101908));
#1355=CARTESIAN_POINT('',(35.006395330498,-4.13027625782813,35.1949523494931));
#1356=CARTESIAN_POINT('',(34.8879232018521,-4.32495587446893,35.2047392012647));
#1357=CARTESIAN_POINT('',(34.6350552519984,-4.70370148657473,35.2257247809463));
#1358=CARTESIAN_POINT('',(34.5006538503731,-4.88776372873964,35.2369240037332));
#1359=CARTESIAN_POINT('',(34.2167861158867,-5.24408312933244,35.2607014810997));
#1360=CARTESIAN_POINT('',(34.0673049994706,-5.41632841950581,35.2732810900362));
#1361=CARTESIAN_POINT('',(33.7543919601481,-5.74767986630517,35.2997683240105));
#1362=CARTESIAN_POINT('',(33.590953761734,-5.90678004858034,35.3136765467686));
#1363=CARTESIAN_POINT('',(33.251346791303,-6.21065031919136,35.3427630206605));
#1364=CARTESIAN_POINT('',(33.0751772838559,-6.35541957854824,35.3579413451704));
#1365=CARTESIAN_POINT('',(32.7114574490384,-6.62954790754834,35.389499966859));
#1366=CARTESIAN_POINT('',(32.5239122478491,-6.75891384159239,35.4058797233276));
#1367=CARTESIAN_POINT('',(32.1380530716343,-7.0018258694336,35.4398380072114));
#1368=CARTESIAN_POINT('',(31.939704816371,-7.11531697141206,35.4574204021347));
#1369=CARTESIAN_POINT('',(31.534311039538,-7.32513617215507,35.4936539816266));
#1370=CARTESIAN_POINT('',(31.3272685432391,-7.42147018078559,35.5123047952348));
#1371=CARTESIAN_POINT('',(30.9058327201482,-7.59638747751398,35.5506054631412));
#1372=CARTESIAN_POINT('',(30.6914372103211,-7.67496544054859,35.5702556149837));
#1373=CARTESIAN_POINT('',(30.2568804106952,-7.81379670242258,35.6104608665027));
#1374=CARTESIAN_POINT('',(30.0367192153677,-7.87405030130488,35.6310159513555));
#1375=CARTESIAN_POINT('',(29.5912731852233,-7.97603714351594,35.6730209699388));
#1376=CARTESIAN_POINT('',(29.3659710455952,-8.01769344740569,35.6944742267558));
#1377=CARTESIAN_POINT('',(28.912726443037,-8.08184498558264,35.7380896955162));
#1378=CARTESIAN_POINT('',(28.6847840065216,-8.10434041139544,35.7602519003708));
#1379=CARTESIAN_POINT('',(28.2280012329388,-8.13001892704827,35.8051576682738));
#1380=CARTESIAN_POINT('',(27.9991614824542,-8.13321302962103,35.8279008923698));
#1381=CARTESIAN_POINT('',(27.5421499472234,-8.12031596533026,35.8738476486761));
#1382=CARTESIAN_POINT('',(27.3139779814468,-8.10423062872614,35.8970510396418));
#1383=CARTESIAN_POINT('',(26.8299434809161,-8.0495138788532,35.9468679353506));
#1384=CARTESIAN_POINT('',(26.5743856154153,-8.00819559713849,35.9735286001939));
#1385=CARTESIAN_POINT('',(26.0688255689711,-7.90153627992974,36.0270123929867));
#1386=CARTESIAN_POINT('',(25.8188144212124,-7.83623755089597,36.0538351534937));
#1387=CARTESIAN_POINT('',(25.5725081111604,-7.75913546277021,36.0806521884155));
#1388=B_SPLINE_CURVE_WITH_KNOTS('',3,(#1298,#1299,#1300,#1301,#1302,#1303,#1304,#1305,#1306,
#1307,#1308,#1309,#1310,#1311,#1312,#1313,#1314,#1315,#1316,#1317,#1318,#1319,#1320,#1321,#1322,
#1323,#1324,#1325,#1326,#1327,#1328,#1329,#1330,#1331,#1332,#1333,#1334,#1335,#1336,#1337,#1338,
#1339,#1340,#1341,#1342,#1343,#1344,#1345,#1346,#1347,#1348,#1349,#1350,#1351,#1352,#1353,#1354,
#1355,#1356,#1357,#1358,#1359,#1360,#1361,#1362,#1363,#1364,#1365,#1366,#1367,#1368,#1369,#1370,
#1371,#1372,#1373,#1374,#1375,#1376,#1377,#1378,#1379,#1380,#1381,#1382,#1383,#1384,#1385,#1386,
#1387),.UNSPECIFIED.,.F.,.F.,(4,2,2,2,2,2,2,2,2,2,2,2,2,2,2,2,2,2,2,2,2,2,2,2,2,2,2,2,2,2,2,2,2,
2,2,2,2,2,2,2,2,2,2,2,4),(0.,0.692358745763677,1.38469055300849,2.0766229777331,2.7685457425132,
3.46081757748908,4.15309899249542,4.84522332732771,5.53734329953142,6.22808259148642,
6.91904724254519,7.60996385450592,8.3008774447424,8.98922667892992,9.67734750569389,
10.3657492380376,11.0541358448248,11.7404642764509,12.4267803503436,13.1122043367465,
13.7974037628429,14.5337892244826,15.2701701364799,15.9533284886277,16.6367088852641,
17.3209825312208,18.0052667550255,18.6891013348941,19.3729491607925,20.0564545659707,
20.7402001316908,21.4246226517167,22.1093545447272,22.7941260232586,23.4785911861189,
24.165371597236,24.8519149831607,25.538663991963,26.2254017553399,26.9149548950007,
27.6045011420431,28.2936539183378,28.9825983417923,29.7621468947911,30.5403267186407),.UNSPECIFIED.);
#1389=CARTESIAN_POINT('',(25.5725080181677,7.75913543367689,36.0806521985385));
#1390=VERTEX_POINT('',#1389);
#1391=EDGE_CURVE('E625',#1390,#1281,#1388,.T.);
#1392=ORIENTED_EDGE('',*,*,#1391,.F.);
#1393=DIRECTION('',(0.,0.,-1.));
#1394=VECTOR('',#1393,1.);
#1395=CARTESIAN_POINT('',(25.5725080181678,7.7591354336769,24.));
#1396=LINE('',#1395,#1394);
#1397=EDGE_CURVE('E657',#1086,#1390,#1396,.F.);
#1398=ORIENTED_EDGE('',*,*,#1397,.F.);
#1399=ORIENTED_EDGE('',*,*,#1087,.F.);
#1400=ORIENTED_EDGE('',*,*,#1288,.T.);
#1401=EDGE_LOOP('',(#1392,#1398,#1399,#1400));
#1402=FACE_BOUND('',#1401,.T.);
#1403=ADVANCED_FACE('F634',(#1402),#1297,.F.);
#1404=CARTESIAN_POINT('',(28.3762271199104,7.62071867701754,54.));
#1405=DIRECTION('',(0.0493089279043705,0.998783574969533,0.));
#1406=DIRECTION('',(-0.998783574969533,0.0493089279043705,0.));
#1407=AXIS2_PLACEMENT_3D('',#1404,#1405,#1406);
#1408=PLANE('',#1407);
#1409=CARTESIAN_POINT('',(-25.0335974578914,10.2575073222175,36.046378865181));
#1410=CARTESIAN_POINT('',(-24.501110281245,10.2312189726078,36.0986049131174));
#1411=CARTESIAN_POINT('',(-23.9686058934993,10.2049297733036,36.1506553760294));
#1412=CARTESIAN_POINT('',(-22.9035552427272,10.1523493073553,36.2543276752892));
#1413=CARTESIAN_POINT('',(-22.3710089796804,10.1260580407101,36.3059495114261));
#1414=CARTESIAN_POINT('',(-20.7732744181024,10.047179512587,36.4600579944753));
#1415=CARTESIAN_POINT('',(-19.7080129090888,9.99458863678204,36.5617853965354));
#1416=CARTESIAN_POINT('',(-17.5742778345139,9.88924830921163,36.762553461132));
#1417=CARTESIAN_POINT('',(-16.5058034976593,9.8364988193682,36.8615859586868));
#1418=CARTESIAN_POINT('',(-14.9027833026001,9.75735934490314,37.0066531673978));
#1419=CARTESIAN_POINT('',(-14.3683947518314,9.73097712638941,37.0544283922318));
#1420=CARTESIAN_POINT('',(-13.2994875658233,9.6782062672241,37.1484946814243));
#1421=CARTESIAN_POINT('',(-12.7649689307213,9.65181762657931,37.1947857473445));
#1422=CARTESIAN_POINT('',(-11.6990171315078,9.5991926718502,37.2851957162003));
#1423=CARTESIAN_POINT('',(-11.1675849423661,9.57295640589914,37.3293261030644));
#1424=CARTESIAN_POINT('',(-10.1045241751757,9.5204741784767,37.4151630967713));
#1425=CARTESIAN_POINT('',(-9.57289559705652,9.49422821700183,37.4568697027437));
#1426=CARTESIAN_POINT('',(-8.50936185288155,9.44172263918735,37.5371265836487));
#1427=CARTESIAN_POINT('',(-7.97745667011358,9.41546302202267,37.5756766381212));
#1428=CARTESIAN_POINT('',(-6.91335987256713,9.36292964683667,37.648645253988));
#1429=CARTESIAN_POINT('',(-6.38116825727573,9.33665588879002,37.6830638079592));
#1430=CARTESIAN_POINT('',(-5.31728763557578,9.2841331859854,37.7464814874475));
#1431=CARTESIAN_POINT('',(-4.78559913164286,9.25788426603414,37.7754889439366));
#1432=CARTESIAN_POINT('',(-3.72189007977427,9.20537003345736,37.8266905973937));
#1433=CARTESIAN_POINT('',(-3.18986953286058,9.1791047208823,37.8488848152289));
#1434=CARTESIAN_POINT('',(-2.12563606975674,9.12656459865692,37.8849543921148));
#1435=CARTESIAN_POINT('',(-1.59342320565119,9.10028979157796,37.8988312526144));
#1436=CARTESIAN_POINT('',(-0.528835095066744,9.04773216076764,37.9170969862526));
#1437=CARTESIAN_POINT('',(0.0035401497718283,9.02144933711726,37.9214859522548));
#1438=CARTESIAN_POINT('',(1.05722336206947,8.96943007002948,37.9203716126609));
#1439=CARTESIAN_POINT('',(1.57853156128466,8.94369361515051,37.9150718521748));
#1440=CARTESIAN_POINT('',(2.62097855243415,8.8922290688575,37.8954583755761));
#1441=CARTESIAN_POINT('',(3.14211734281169,8.86650097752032,37.8811445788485));
#1442=CARTESIAN_POINT('',(4.18420485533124,8.81505417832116,37.8446435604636));
#1443=CARTESIAN_POINT('',(4.70515352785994,8.78933547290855,37.8224549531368));
#1444=CARTESIAN_POINT('',(5.74673187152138,8.73791381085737,37.7716211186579));
#1445=CARTESIAN_POINT('',(6.26736154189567,8.71221085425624,37.7429758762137));
#1446=CARTESIAN_POINT('',(7.30910610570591,8.66078098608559,37.6805448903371));
#1447=CARTESIAN_POINT('',(7.83022052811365,8.63505409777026,37.646751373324));
#1448=CARTESIAN_POINT('',(8.87217533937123,8.58361384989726,37.5752130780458));
#1449=CARTESIAN_POINT('',(9.39301572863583,8.55790049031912,37.5374683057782));
#1450=CARTESIAN_POINT('',(10.4344305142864,8.50648690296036,37.4589442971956));
#1451=CARTESIAN_POINT('',(10.9550049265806,8.48078667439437,37.4181652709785));
#1452=CARTESIAN_POINT('',(11.9959637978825,8.42939559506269,37.3342591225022));
#1453=CARTESIAN_POINT('',(12.5163482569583,8.40370474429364,37.2911320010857));
#1454=CARTESIAN_POINT('',(14.0834811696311,8.32633698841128,37.158520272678));
#1455=CARTESIAN_POINT('',(15.1299970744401,8.2746715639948,37.0662874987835));
#1456=CARTESIAN_POINT('',(17.2226329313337,8.17136026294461,36.8773215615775));
#1457=CARTESIAN_POINT('',(18.2687528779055,8.11971438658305,36.7805883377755));
#1458=CARTESIAN_POINT('',(20.3579310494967,8.01657378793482,36.5844316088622));
#1459=CARTESIAN_POINT('',(21.4009900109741,7.96507902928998,36.4850159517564));
#1460=CARTESIAN_POINT('',(22.9654220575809,7.88784461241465,36.3343918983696));
#1461=CARTESIAN_POINT('',(23.4868675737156,7.86210137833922,36.2839343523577));
#1462=CARTESIAN_POINT('',(24.5297171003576,7.81061695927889,36.1825937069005));
#1463=CARTESIAN_POINT('',(25.0511211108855,7.78487577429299,36.1317106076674));
#1464=CARTESIAN_POINT('',(25.5725080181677,7.75913543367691,36.0806521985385));
#1465=B_SPLINE_CURVE_WITH_KNOTS('',3,(#1409,#1410,#1411,#1412,#1413,#1414,#1415,#1416,#1417,
#1418,#1419,#1420,#1421,#1422,#1423,#1424,#1425,#1426,#1427,#1428,#1429,#1430,#1431,#1432,#1433,
#1434,#1435,#1436,#1437,#1438,#1439,#1440,#1441,#1442,#1443,#1444,#1445,#1446,#1447,#1448,#1449,
#1450,#1451,#1452,#1453,#1454,#1455,#1456,#1457,#1458,#1459,#1460,#1461,#1462,#1463,#1464),
.UNSPECIFIED.,.F.,.F.,(4,2,2,2,2,2,2,2,2,2,2,2,2,2,2,2,2,2,2,2,2,2,2,2,2,2,2,4),(0.,
1.60706287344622,3.2141265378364,6.42832196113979,9.65136348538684,11.2628663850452,
12.8743675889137,14.4760824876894,16.077797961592,17.6796252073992,19.2814553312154,
20.8807985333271,22.4801368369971,24.0791863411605,25.6782201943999,27.2440460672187,
28.8098859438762,30.3760014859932,31.9421207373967,33.5106286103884,35.0791341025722,
36.647531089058,38.2159275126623,41.3714348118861,44.5269845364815,47.6741332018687,
49.2476727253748,50.8212114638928),.UNSPECIFIED.);
#1466=EDGE_CURVE('E608',#1117,#1390,#1465,.T.);
#1467=ORIENTED_EDGE('',*,*,#1466,.F.);
#1468=ORIENTED_EDGE('',*,*,#1118,.F.);
#1469=ORIENTED_EDGE('',*,*,#1093,.F.);
#1470=ORIENTED_EDGE('',*,*,#1397,.T.);
#1471=EDGE_LOOP('',(#1467,#1468,#1469,#1470));
#1472=FACE_BOUND('',#1471,.T.);
#1473=ADVANCED_FACE('F602',(#1472),#1408,.F.);
#1474=CARTESIAN_POINT('',(0.,0.,34.8901446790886));
#1475=DIRECTION('',(0.,0.,-1.));
#1476=DIRECTION('',(-1.,0.,0.));
#1477=AXIS2_PLACEMENT_3D('',#1474,#1475,#1476);
#1478=CONICAL_SURFACE('',#1477,38.1823574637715,1.46727165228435);
#1479=ORIENTED_EDGE('',*,*,#1282,.T.);
#1480=ORIENTED_EDGE('',*,*,#1205,.T.);
#1481=ORIENTED_EDGE('',*,*,#1466,.T.);
#1482=ORIENTED_EDGE('',*,*,#1391,.T.);
#1483=EDGE_LOOP('',(#1479,#1480,#1481,#1482));
#1484=FACE_BOUND('',#1483,.T.);
#1485=CARTESIAN_POINT('',(0.,0.,34.8901446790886));
#1486=DIRECTION('',(0.,0.,1.));
#1487=DIRECTION('',(0.,1.,0.));
#1488=AXIS2_PLACEMENT_3D('',#1485,#1486,#1487);
#1489=CIRCLE('',#1488,38.1823574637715);
#1490=CARTESIAN_POINT('',(0.,38.1823574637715,34.8901446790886));
#1491=VERTEX_POINT('',#1490);
#1492=EDGE_CURVE('E772',#1491,#1491,#1489,.F.);
#1493=ORIENTED_EDGE('',*,*,#1492,.F.);
#1494=EDGE_LOOP('',(#1493));
#1495=FACE_BOUND('',#1494,.T.);
#1496=ADVANCED_FACE('F591',(#1484,#1495),#1478,.T.);
#1497=CARTESIAN_POINT('',(0.,0.,31.2099540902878));
#1498=DIRECTION('',(0.,0.,1.));
#1499=DIRECTION('',(0.,1.,0.));
#1500=AXIS2_PLACEMENT_3D('',#1497,#1498,#1499);
#1501=TOROIDAL_SURFACE('',#1500,37.8,3.7);
#1502=CARTESIAN_POINT('',(0.,0.,31.2099540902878));
#1503=DIRECTION('',(0.,0.,-1.));
#1504=DIRECTION('',(-1.,0.,0.));
#1505=AXIS2_PLACEMENT_3D('',#1502,#1503,#1504);
#1506=CIRCLE('',#1505,41.5);
#1507=CARTESIAN_POINT('',(-41.5,0.,31.2099540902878));
#1508=VERTEX_POINT('',#1507);
#1509=EDGE_CURVE('E584',#1508,#1508,#1506,.T.);
#1510=ORIENTED_EDGE('',*,*,#1509,.F.);
#1511=EDGE_LOOP('',(#1510));
#1512=FACE_BOUND('',#1511,.T.);
#1513=ORIENTED_EDGE('',*,*,#1492,.T.);
#1514=EDGE_LOOP('',(#1513));
#1515=FACE_BOUND('',#1514,.T.);
#1516=ADVANCED_FACE('F587',(#1512,#1515),#1501,.T.);
#1517=CARTESIAN_POINT('',(0.,0.,26.0112270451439));
#1518=DIRECTION('',(0.,0.,-1.));
#1519=DIRECTION('',(-1.,0.,0.));
#1520=AXIS2_PLACEMENT_3D('',#1517,#1518,#1519);
#1521=CYLINDRICAL_SURFACE('',#1520,41.5);
#1522=CARTESIAN_POINT('',(0.,0.,20.8125));
#1523=DIRECTION('',(0.,0.,1.));
#1524=DIRECTION('',(0.,1.,0.));
#1525=AXIS2_PLACEMENT_3D('',#1522,#1523,#1524);
#1526=CIRCLE('',#1525,41.5);
#1527=CARTESIAN_POINT('',(0.,41.5,20.8125));
#1528=VERTEX_POINT('',#1527);
#1529=EDGE_CURVE('E572',#1528,#1528,#1526,.F.);
#1530=ORIENTED_EDGE('',*,*,#1529,.F.);
#1531=EDGE_LOOP('',(#1530));
#1532=FACE_BOUND('',#1531,.T.);
#1533=ORIENTED_EDGE('',*,*,#1509,.T.);
#1534=EDGE_LOOP('',(#1533));
#1535=FACE_BOUND('',#1534,.T.);
#1536=ADVANCED_FACE('F547',(#1532,#1535),#1521,.T.);
#1537=CARTESIAN_POINT('',(0.,0.,20.8125));
#1538=DIRECTION('',(0.,0.,1.));
#1539=DIRECTION('',(0.,1.,0.));
#1540=AXIS2_PLACEMENT_3D('',#1537,#1538,#1539);
#1541=TOROIDAL_SURFACE('',#1540,39.1875,2.3125);
#1542=ORIENTED_EDGE('',*,*,#1529,.T.);
#1543=EDGE_LOOP('',(#1542));
#1544=FACE_BOUND('',#1543,.T.);
#1545=CARTESIAN_POINT('',(0.,0.,18.5));
#1546=DIRECTION('',(0.,0.,1.));
#1547=DIRECTION('',(0.,-1.,0.));
#1548=AXIS2_PLACEMENT_3D('',#1545,#1546,#1547);
#1549=CIRCLE('',#1548,39.1875);
#1550=CARTESIAN_POINT('',(0.,39.1875,18.5));
#1551=VERTEX_POINT('',#1550);
#1552=CARTESIAN_POINT('',(0.,-39.1875,18.5));
#1553=VERTEX_POINT('',#1552);
#1554=EDGE_CURVE('E567',#1551,#1553,#1549,.F.);
#1555=ORIENTED_EDGE('',*,*,#1554,.F.);
#1556=CARTESIAN_POINT('',(0.,0.,18.5));
#1557=DIRECTION('',(0.,0.,1.));
#1558=DIRECTION('',(0.,1.,0.));
#1559=AXIS2_PLACEMENT_3D('',#1556,#1557,#1558);
#1560=CIRCLE('',#1559,39.1875);
#1561=CARTESIAN_POINT('',(-39.1875,0.,18.5));
#1562=VERTEX_POINT('',#1561);
#1563=EDGE_CURVE('E678',#1562,#1551,#1560,.F.);
#1564=ORIENTED_EDGE('',*,*,#1563,.F.);
#1565=CARTESIAN_POINT('',(0.,0.,18.5));
#1566=DIRECTION('',(0.,0.,1.));
#1567=DIRECTION('',(-1.,0.,0.));
#1568=AXIS2_PLACEMENT_3D('',#1565,#1566,#1567);
#1569=CIRCLE('',#1568,39.1875);
#1570=EDGE_CURVE('E688',#1553,#1562,#1569,.F.);
#1571=ORIENTED_EDGE('',*,*,#1570,.F.);
#1572=EDGE_LOOP('',(#1555,#1564,#1571));
#1573=FACE_BOUND('',#1572,.T.);
#1574=ADVANCED_FACE('F535',(#1544,#1573),#1541,.T.);
#1575=CARTESIAN_POINT('',(-38.68375,0.,18.5));
#1576=DIRECTION('',(0.,0.,-1.));
#1577=DIRECTION('',(-1.,0.,0.));
#1578=AXIS2_PLACEMENT_3D('',#1575,#1576,#1577);
#1579=PLANE('',#1578);
#1580=CARTESIAN_POINT('',(0.,0.,18.5));
#1581=DIRECTION('',(0.,0.,-1.));
#1582=DIRECTION('',(-1.,0.,0.));
#1583=AXIS2_PLACEMENT_3D('',#1580,#1581,#1582);
#1584=CIRCLE('',#1583,38.18);
#1585=CARTESIAN_POINT('',(-38.18,0.,18.5));
#1586=VERTEX_POINT('',#1585);
#1587=EDGE_CURVE('E744',#1586,#1586,#1584,.F.);
#1588=ORIENTED_EDGE('',*,*,#1587,.T.);
#1589=EDGE_LOOP('',(#1588));
#1590=FACE_BOUND('',#1589,.T.);
#1591=ORIENTED_EDGE('',*,*,#1563,.T.);
#1592=ORIENTED_EDGE('',*,*,#1554,.T.);
#1593=ORIENTED_EDGE('',*,*,#1570,.T.);
#1594=EDGE_LOOP('',(#1591,#1592,#1593));
#1595=FACE_BOUND('',#1594,.T.);
#1596=ADVANCED_FACE('F546',(#1590,#1595),#1579,.T.);
#1597=CARTESIAN_POINT('',(0.,0.,20.3505));
#1598=DIRECTION('',(0.,0.,-1.));
#1599=DIRECTION('',(-1.,0.,0.));
#1600=AXIS2_PLACEMENT_3D('',#1597,#1598,#1599);
#1601=CYLINDRICAL_SURFACE('',#1600,38.18);
#1602=ORIENTED_EDGE('',*,*,#1587,.F.);
#1603=EDGE_LOOP('',(#1602));
#1604=FACE_BOUND('',#1603,.T.);
#1605=CARTESIAN_POINT('',(0.,0.,22.201));
#1606=DIRECTION('',(0.,0.,-1.));
#1607=DIRECTION('',(-1.,0.,0.));
#1608=AXIS2_PLACEMENT_3D('',#1605,#1606,#1607);
#1609=CIRCLE('',#1608,38.18);
#1610=CARTESIAN_POINT('',(-38.18,0.,22.201));
#1611=VERTEX_POINT('',#1610);
#1612=EDGE_CURVE('E738',#1611,#1611,#1609,.T.);
#1613=ORIENTED_EDGE('',*,*,#1612,.F.);
#1614=EDGE_LOOP('',(#1613));
#1615=FACE_BOUND('',#1614,.T.);
#1616=ADVANCED_FACE('F705',(#1604,#1615),#1601,.F.);
#1617=CARTESIAN_POINT('',(-25.34,0.,22.201));
#1618=DIRECTION('',(0.,0.,-1.));
#1619=DIRECTION('',(0.,-1.,0.));
#1620=AXIS2_PLACEMENT_3D('',#1617,#1618,#1619);
#1621=PLANE('',#1620);
#1622=CARTESIAN_POINT('',(0.,0.,22.201));
#1623=DIRECTION('',(0.,0.,-1.));
#1624=DIRECTION('',(-1.,0.,0.));
#1625=AXIS2_PLACEMENT_3D('',#1622,#1623,#1624);
#1626=CIRCLE('',#1625,12.5);
#1627=CARTESIAN_POINT('',(-12.5,0.,22.201));
#1628=VERTEX_POINT('',#1627);
#1629=EDGE_CURVE('E528',#1628,#1628,#1626,.F.);
#1630=ORIENTED_EDGE('',*,*,#1629,.T.);
#1631=EDGE_LOOP('',(#1630));
#1632=FACE_BOUND('',#1631,.T.);
#1633=ORIENTED_EDGE('',*,*,#1612,.T.);
#1634=EDGE_LOOP('',(#1633));
#1635=FACE_BOUND('',#1634,.T.);
#1636=ADVANCED_FACE('F723',(#1632,#1635),#1621,.T.);
#1637=CARTESIAN_POINT('',(0.,0.,11.2005));
#1638=DIRECTION('',(0.,0.,-1.));
#1639=DIRECTION('',(-1.,0.,0.));
#1640=AXIS2_PLACEMENT_3D('',#1637,#1638,#1639);
#1641=CYLINDRICAL_SURFACE('',#1640,12.5);
#1642=ORIENTED_EDGE('',*,*,#1629,.F.);
#1643=EDGE_LOOP('',(#1642));
#1644=FACE_BOUND('',#1643,.T.);
#1645=CARTESIAN_POINT('',(0.,0.,0.199999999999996));
#1646=DIRECTION('',(0.,0.,-1.));
#1647=DIRECTION('',(-1.,0.,0.));
#1648=AXIS2_PLACEMENT_3D('',#1645,#1646,#1647);
#1649=CIRCLE('',#1648,12.5);
#1650=CARTESIAN_POINT('',(-12.5,0.,0.199999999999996));
#1651=VERTEX_POINT('',#1650);
#1652=EDGE_CURVE('E740',#1651,#1651,#1649,.F.);
#1653=ORIENTED_EDGE('',*,*,#1652,.T.);
#1654=EDGE_LOOP('',(#1653));
#1655=FACE_BOUND('',#1654,.T.);
#1656=ADVANCED_FACE('F719',(#1644,#1655),#1641,.T.);
#1657=CARTESIAN_POINT('',(-10.75,0.,0.199999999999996));
#1658=DIRECTION('',(0.,0.,-1.));
#1659=DIRECTION('',(-1.,0.,0.));
#1660=AXIS2_PLACEMENT_3D('',#1657,#1658,#1659);
#1661=PLANE('',#1660);
#1662=CARTESIAN_POINT('',(0.,0.,0.199999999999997));
#1663=DIRECTION('',(0.,0.,-1.));
#1664=DIRECTION('',(-1.,0.,0.));
#1665=AXIS2_PLACEMENT_3D('',#1662,#1663,#1664);
#1666=CIRCLE('',#1665,9.);
#1667=CARTESIAN_POINT('',(-9.00000000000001,0.,0.199999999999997));
#1668=VERTEX_POINT('',#1667);
#1669=EDGE_CURVE('E750',#1668,#1668,#1666,.F.);
#1670=ORIENTED_EDGE('',*,*,#1669,.T.);
#1671=EDGE_LOOP('',(#1670));
#1672=FACE_BOUND('',#1671,.T.);
#1673=ORIENTED_EDGE('',*,*,#1652,.F.);
#1674=EDGE_LOOP('',(#1673));
#1675=FACE_BOUND('',#1674,.T.);
#1676=ADVANCED_FACE('F707',(#1672,#1675),#1661,.T.);
#1677=CARTESIAN_POINT('',(0.,0.,0.1));
#1678=DIRECTION('',(0.,0.,-1.));
#1679=DIRECTION('',(-1.,0.,0.));
#1680=AXIS2_PLACEMENT_3D('',#1677,#1678,#1679);
#1681=CYLINDRICAL_SURFACE('',#1680,9.);
#1682=ORIENTED_EDGE('',*,*,#1669,.F.);
#1683=EDGE_LOOP('',(#1682));
#1684=FACE_BOUND('',#1683,.T.);
#1685=CARTESIAN_POINT('',(0.,0.,0.));
#1686=DIRECTION('',(0.,0.,-1.));
#1687=DIRECTION('',(-1.,0.,0.));
#1688=AXIS2_PLACEMENT_3D('',#1685,#1686,#1687);
#1689=CIRCLE('',#1688,9.);
#1690=CARTESIAN_POINT('',(-9.00000000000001,0.,0.));
#1691=VERTEX_POINT('',#1690);
#1692=EDGE_CURVE('E580',#1691,#1691,#1689,.F.);
#1693=ORIENTED_EDGE('',*,*,#1692,.T.);
#1694=EDGE_LOOP('',(#1693));
#1695=FACE_BOUND('',#1694,.T.);
#1696=ADVANCED_FACE('F549',(#1684,#1695),#1681,.T.);
#1697=CARTESIAN_POINT('',(-6.63333333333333,0.,0.));
#1698=DIRECTION('',(0.,0.,-1.));
#1699=DIRECTION('',(0.,-1.,0.));
#1700=AXIS2_PLACEMENT_3D('',#1697,#1698,#1699);
#1701=PLANE('',#1700);
#1702=CARTESIAN_POINT('',(0.,0.,0.));
#1703=DIRECTION('',(0.,0.,-1.));
#1704=DIRECTION('',(-1.,0.,0.));
#1705=AXIS2_PLACEMENT_3D('',#1702,#1703,#1704);
#1706=CIRCLE('',#1705,4.26666666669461);
#1707=CARTESIAN_POINT('',(-4.26666666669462,0.,0.));
#1708=VERTEX_POINT('',#1707);
#1709=EDGE_CURVE('E581',#1708,#1708,#1706,.F.);
#1710=ORIENTED_EDGE('',*,*,#1709,.T.);
#1711=EDGE_LOOP('',(#1710));
#1712=FACE_BOUND('',#1711,.T.);
#1713=ORIENTED_EDGE('',*,*,#1692,.F.);
#1714=EDGE_LOOP('',(#1713));
#1715=FACE_BOUND('',#1714,.T.);
#1716=ADVANCED_FACE('F551',(#1712,#1715),#1701,.T.);
#1717=CARTESIAN_POINT('',(0.,0.,0.));
#1718=DIRECTION('',(0.,0.,-1.));
#1719=DIRECTION('',(-1.,0.,0.));
#1720=AXIS2_PLACEMENT_3D('',#1717,#1718,#1719);
#1721=CONICAL_SURFACE('',#1720,4.26666666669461,0.785398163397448);
#1722=ORIENTED_EDGE('',*,*,#1709,.F.);
#1723=EDGE_LOOP('',(#1722));
#1724=FACE_BOUND('',#1723,.T.);
#1725=CARTESIAN_POINT('',(0.,0.,0.266666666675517));
#1726=DIRECTION('',(0.,0.,-1.));
#1727=DIRECTION('',(-1.,0.,0.));
#1728=AXIS2_PLACEMENT_3D('',#1725,#1726,#1727);
#1729=CIRCLE('',#1728,4.00000000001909);
#1730=CARTESIAN_POINT('',(-4.0000000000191,0.,0.266666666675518));
#1731=VERTEX_POINT('',#1730);
#1732=EDGE_CURVE('E768',#1731,#1731,#1729,.T.);
#1733=ORIENTED_EDGE('',*,*,#1732,.F.);
#1734=EDGE_LOOP('',(#1733));
#1735=FACE_BOUND('',#1734,.T.);
#1736=ADVANCED_FACE('F593',(#1724,#1735),#1721,.F.);
#1737=CARTESIAN_POINT('',(0.,0.,8.5));
#1738=DIRECTION('',(0.,0.,-1.));
#1739=DIRECTION('',(-1.,0.,0.));
#1740=AXIS2_PLACEMENT_3D('',#1737,#1738,#1739);
#1741=CYLINDRICAL_SURFACE('',#1740,4.);
#1742=ORIENTED_EDGE('',*,*,#1732,.T.);
#1743=EDGE_LOOP('',(#1742));
#1744=FACE_BOUND('',#1743,.T.);
#1745=CARTESIAN_POINT('',(0.,0.,16.7333333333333));
#1746=DIRECTION('',(0.,0.,-1.));
#1747=DIRECTION('',(-1.,0.,0.));
#1748=AXIS2_PLACEMENT_3D('',#1745,#1746,#1747);
#1749=CIRCLE('',#1748,4.);
#1750=CARTESIAN_POINT('',(-4.00000000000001,0.,16.7333333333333));
#1751=VERTEX_POINT('',#1750);
#1752=EDGE_CURVE('E632',#1751,#1751,#1749,.T.);
#1753=ORIENTED_EDGE('',*,*,#1752,.F.);
#1754=EDGE_LOOP('',(#1753));
#1755=FACE_BOUND('',#1754,.T.);
#1756=ADVANCED_FACE('F594',(#1744,#1755),#1741,.F.);
#1757=CARTESIAN_POINT('',(0.,0.,16.9999999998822));
#1758=DIRECTION('',(0.,0.,1.));
#1759=DIRECTION('',(1.,0.,0.));
#1760=AXIS2_PLACEMENT_3D('',#1757,#1758,#1759);
#1761=CONICAL_SURFACE('',#1760,4.26666666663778,0.78539816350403);
#1762=ORIENTED_EDGE('',*,*,#1752,.T.);
#1763=EDGE_LOOP('',(#1762));
#1764=FACE_BOUND('',#1763,.T.);
#1765=CARTESIAN_POINT('',(0.,0.,16.999999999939));
#1766=DIRECTION('',(0.,0.,1.));
#1767=DIRECTION('',(1.,0.,0.));
#1768=AXIS2_PLACEMENT_3D('',#1765,#1766,#1767);
#1769=CIRCLE('',#1768,4.26666666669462);
#1770=CARTESIAN_POINT('',(4.26666666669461,0.,16.999999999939));
#1771=VERTEX_POINT('',#1770);
#1772=EDGE_CURVE('E653',#1771,#1771,#1769,.F.);
#1773=ORIENTED_EDGE('',*,*,#1772,.F.);
#1774=EDGE_LOOP('',(#1773));
#1775=FACE_BOUND('',#1774,.T.);
#1776=ADVANCED_FACE('F597',(#1764,#1775),#1761,.F.);
#1777=CARTESIAN_POINT('',(-6.13333333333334,0.,17.));
#1778=DIRECTION('',(0.,0.,1.));
#1779=DIRECTION('',(0.,1.,0.));
#1780=AXIS2_PLACEMENT_3D('',#1777,#1778,#1779);
#1781=PLANE('',#1780);
#1782=CARTESIAN_POINT('',(0.,0.,17.));
#1783=DIRECTION('',(0.,0.,-1.));
#1784=DIRECTION('',(-1.,0.,0.));
#1785=AXIS2_PLACEMENT_3D('',#1782,#1783,#1784);
#1786=CIRCLE('',#1785,8.);
#1787=CARTESIAN_POINT('',(-8.00000000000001,0.,17.));
#1788=VERTEX_POINT('',#1787);
#1789=EDGE_CURVE('E671',#1788,#1788,#1786,.F.);
#1790=ORIENTED_EDGE('',*,*,#1789,.T.);
#1791=EDGE_LOOP('',(#1790));
#1792=FACE_BOUND('',#1791,.T.);
#1793=ORIENTED_EDGE('',*,*,#1772,.T.);
#1794=EDGE_LOOP('',(#1793));
#1795=FACE_BOUND('',#1794,.T.);
#1796=ADVANCED_FACE('F1046',(#1792,#1795),#1781,.T.);
#1797=CARTESIAN_POINT('',(0.,0.,17.85));
#1798=DIRECTION('',(0.,0.,-1.));
#1799=DIRECTION('',(-1.,0.,0.));
#1800=AXIS2_PLACEMENT_3D('',#1797,#1798,#1799);
#1801=CYLINDRICAL_SURFACE('',#1800,8.);
#1802=ORIENTED_EDGE('',*,*,#1789,.F.);
#1803=EDGE_LOOP('',(#1802));
#1804=FACE_BOUND('',#1803,.T.);
#1805=CARTESIAN_POINT('',(0.,0.,18.7));
#1806=DIRECTION('',(0.,0.,-1.));
#1807=DIRECTION('',(-1.,0.,0.));
#1808=AXIS2_PLACEMENT_3D('',#1805,#1806,#1807);
#1809=CIRCLE('',#1808,8.);
#1810=CARTESIAN_POINT('',(-8.00000000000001,0.,18.7));
#1811=VERTEX_POINT('',#1810);
#1812=EDGE_CURVE('E238',#1811,#1811,#1809,.T.);
#1813=ORIENTED_EDGE('',*,*,#1812,.F.);
#1814=EDGE_LOOP('',(#1813));
#1815=FACE_BOUND('',#1814,.T.);
#1816=ADVANCED_FACE('F1056',(#1804,#1815),#1801,.F.);
#1817=CARTESIAN_POINT('',(-4.,0.,18.7));
#1818=DIRECTION('',(0.,0.,-1.));
#1819=DIRECTION('',(0.,-1.,0.));
#1820=AXIS2_PLACEMENT_3D('',#1817,#1818,#1819);
#1821=PLANE('',#1820);
#1822=ORIENTED_EDGE('',*,*,#1812,.T.);
#1823=EDGE_LOOP('',(#1822));
#1824=FACE_BOUND('',#1823,.T.);
#1825=ADVANCED_FACE('F251',(#1824),#1821,.T.);
#1826=CLOSED_SHELL('',(#46,#66,#394,#414,#475,#523,#556,#596,#618,#628,#650,#660,#680,#740,#795,
#850,#870,#890,#910,#935,#960,#977,#989,#1007,#1021,#1033,#1042,#1051,#1060,#1105,#1215,#1292,
#1403,#1473,#1496,#1516,#1536,#1574,#1596,#1616,#1636,#1656,#1676,#1696,#1716,#1736,#1756,#1776,
#1796,#1816,#1825));
#1827=CARTESIAN_POINT('',(33.5,0.,24.));
#1828=DIRECTION('',(0.,0.,1.));
#1829=DIRECTION('',(0.,1.,0.));
#1830=AXIS2_PLACEMENT_3D('',#1827,#1828,#1829);
#1831=CIRCLE('',#1830,1.5);
#1832=CARTESIAN_POINT('',(33.5,1.5,24.));
#1833=VERTEX_POINT('',#1832);
#1834=EDGE_CURVE('E9',#1833,#1833,#1831,.T.);
#1835=ORIENTED_EDGE('',*,*,#1834,.T.);
#1836=EDGE_LOOP('',(#1835));
#1837=FACE_BOUND('',#1836,.T.);
#1838=ADVANCED_FACE('F338',(#1837),#1056,.T.);
#1839=CARTESIAN_POINT('',(33.5,0.,24.7000000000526));
#1840=DIRECTION('',(0.,0.,-1.));
#1841=DIRECTION('',(0.,-1.,0.));
#1842=AXIS2_PLACEMENT_3D('',#1839,#1840,#1841);
#1843=CONICAL_SURFACE('',#1842,1.49999999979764,1.04719755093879);
#1844=CARTESIAN_POINT('',(33.5000000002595,0.,25.5660254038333));
#1845=VERTEX_POINT('',#1844);
#1846=VERTEX_LOOP('',#1845);
#1847=FACE_BOUND('',#1846,.T.);
#1848=CARTESIAN_POINT('',(33.5,0.,24.7));
#1849=DIRECTION('',(0.,0.,1.));
#1850=DIRECTION('',(0.,1.,0.));
#1851=AXIS2_PLACEMENT_3D('',#1848,#1849,#1850);
#1852=CIRCLE('',#1851,1.5);
#1853=CARTESIAN_POINT('',(33.5,1.5,24.7));
#1854=VERTEX_POINT('',#1853);
#1855=EDGE_CURVE('E220',#1854,#1854,#1852,.F.);
#1856=ORIENTED_EDGE('',*,*,#1855,.T.);
#1857=EDGE_LOOP('',(#1856));
#1858=FACE_BOUND('',#1857,.T.);
#1859=ADVANCED_FACE('F336',(#1847,#1858),#1843,.F.);
#1860=CARTESIAN_POINT('',(33.5,0.,24.35));
#1861=DIRECTION('',(0.,0.,1.));
#1862=DIRECTION('',(0.,1.,0.));
#1863=AXIS2_PLACEMENT_3D('',#1860,#1861,#1862);
#1864=CYLINDRICAL_SURFACE('',#1863,1.5);
#1865=ORIENTED_EDGE('',*,*,#1834,.F.);
#1866=EDGE_LOOP('',(#1865));
#1867=FACE_BOUND('',#1866,.T.);
#1868=ORIENTED_EDGE('',*,*,#1855,.F.);
#1869=EDGE_LOOP('',(#1868));
#1870=FACE_BOUND('',#1869,.T.);
#1871=ADVANCED_FACE('F334',(#1867,#1870),#1864,.F.);
#1872=CLOSED_SHELL('',(#1838,#1859,#1871));
#1873=ORIENTED_CLOSED_SHELL('',*,#1872,.T.);
#1874=BREP_WITH_VOIDS('B1',#1826,(#1873));
#1875=ADVANCED_BREP_SHAPE_REPRESENTATION('',(#18,#1874),#14);
#1876=SHAPE_DEFINITION_REPRESENTATION(#9,#1875);
ENDSEC;
END-ISO-10303-21;
